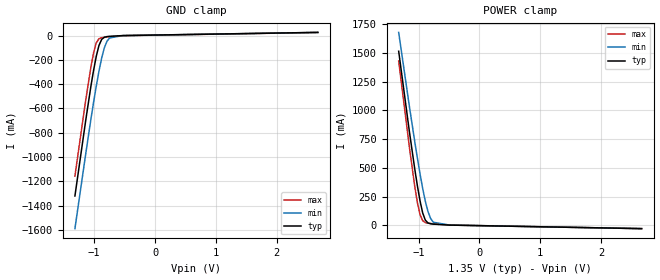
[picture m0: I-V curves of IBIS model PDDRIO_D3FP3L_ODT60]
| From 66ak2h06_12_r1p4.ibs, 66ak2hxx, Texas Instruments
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|   Model PDDRIO_D3FP3L_ODT60
[Model] PDDRIO_D3FP3L_ODT60
Model_type   Input
Polarity   Non-Inverting
Enable   Active-High
C_comp   3.326pF   3.253pF   3.436pF
C_comp_pullup   616.851fF   581.993fF   679.460fF
C_comp_pulldown 2.704pF   2.666pF   2.751pF
Vinh = 810.000mV
Vinl = 540.000mV
[Temperature Range]   25.000   125.000   -40.000
[Voltage Range]   1.350V   1.283V   1.450V
[GND Clamp Reference]   0.00V   0.00V   0.00V
|[C Comp Corner]
| variable   typ   min   max
|C_comp 3.326pF   3.436pF   3.253pF
|C_comp_pullup 616.851fF   679.460fF   581.993fF
|C_comp_pulldown 2.704pF   2.751pF   2.666pF
[POWER Clamp Reference]   1.350V   1.283V   1.450V
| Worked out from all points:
|   GND clamp passes 1 mA (typ) near -0.55 V on its own axis
|   POWER clamp passes 1 mA (typ) near -0.48 V on its own axis
[GND Clamp]
-1.318V   -1.321A    -1.59A     -1.157A
-1.142V   -704.5mA   -980.5mA   -537.9mA
-1.055V   -417.5mA   -689mA     -259.1mA
-1.011V   -286.6mA   -549.7mA   -142.2mA
-966.7mV  -171.3mA   -417.3mA   -60.4mA
-922.7mV  -82.79mA   -295mA     -26.53mA
-878.8mV  -32.67mA   -187.6mA   -18.22mA
-834.9mV  -14.54mA   -102.8mA   -15.06mA
-790.9mV  -9.105mA   -47.54mA   -12.64mA
-747mV    -6.761mA   -19.93mA   -10.37mA
-527.3mV  -543.3uA   -558.5uA   -1.352mA
2.68V     25.6mA     25.48mA    24.97mA
[Power Clamp]
-1.33V    1.516A     1.68A      1.431A
-1.155V   820.9mA    1.04A      685.2mA
-1.067V   496mA      734.4mA    345mA
-1.023V   346.5mA    588.3mA    199.9mA
-978.8mV  213mA      449.2mA    92.62mA
-934.9mV  107.4mA    320.6mA    39.25mA
-890.9mV  43.96mA    207.7mA    22.53mA
-847mV    19.57mA    117.9mA    17.71mA
-803mV    12.4mA     57.72mA    14.99mA
-759.1mV  9.593mA    25.83mA    12.61mA
-495.5mV  1.233mA    1.543mA    1.65mA
2.668V    -29.53mA   -29.66mA   -29.82mA
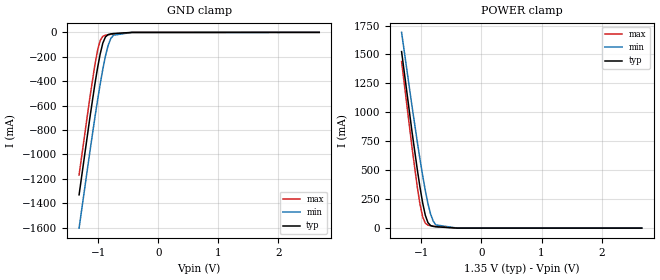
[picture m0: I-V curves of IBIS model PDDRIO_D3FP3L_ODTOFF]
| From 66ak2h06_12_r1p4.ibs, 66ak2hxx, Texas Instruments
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|   Model PDDRIO_D3FP3L_ODTOFF
[Model] PDDRIO_D3FP3L_ODTOFF
Model_type   Input
Polarity   Non-Inverting
Enable   Active-High
C_comp   3.244pF   3.179pF   3.326pF
C_comp_pullup   538.140fF   513.465fF   565.951fF
C_comp_pulldown 2.701pF   2.661pF   2.755pF
Vinh = 810.000mV
Vinl = 540.000mV
[Temperature Range]   25.000   125.000   -40.000
[Voltage Range]   1.350V   1.283V   1.450V
[GND Clamp Reference]   0.00V   0.00V   0.00V
|[C Comp Corner]
| variable   typ   min   max
|C_comp 3.244pF   3.326pF   3.179pF
|C_comp_pullup 538.140fF   565.951fF   513.465fF
|C_comp_pulldown 2.701pF   2.755pF   2.661pF
[POWER Clamp Reference]   1.350V   1.283V   1.450V
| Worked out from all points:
|   GND clamp passes 1 mA (typ) near -0.49 V on its own axis
|   POWER clamp passes 1 mA (typ) near -0.46 V on its own axis
[GND Clamp]
-1.318V   -1.332A    -1.605A    -1.169A
-1.142V   -713.1mA   -991.3mA   -546.4mA
-1.055V   -424.6mA   -698mA     -266.3mA
-1.011V   -292.9mA   -557.9mA   -149mA
-966.7mV  -177mA     -424.6mA   -66.54mA
-922.7mV  -87.81mA   -301.3mA   -32.09mA
-878.8mV  -37.14mA   -193.2mA   -23.25mA
-834.9mV  -18.49mA   -107.6mA   -19.58mA
-790.9mV  -12.57mA   -51.47mA   -16.65mA
-747mV    -9.756mA   -23.13mA   -13.9mA
-439.4mV  -371uA     -394.7uA   -656.8uA
2.68V     4.17nA     252.6nA    716.2pA
[Power Clamp]
-1.33V    1.525A     1.691A     1.439A
-1.155V   827.2mA    1.048A     691.5mA
-1.067V   501.3mA    740.6mA    350.5mA
-1.023V   351.3mA    593.8mA    204.8mA
-978.8mV  217.4mA    454mA      97mA
-934.9mV  111.2mA    324.7mA    43.08mA
-890.9mV  47.28mA    211.3mA    25.9mA
-847mV    22.44mA    121mA      20.68mA
-803mV    14.88mA    60.26mA    17.58mA
-759.1mV  11.71mA    27.92mA    14.82mA
-407.6mV  326.4uA    576uA      395.5uA
2.668V    -7.545nA   -288.5nA   -1.636nA
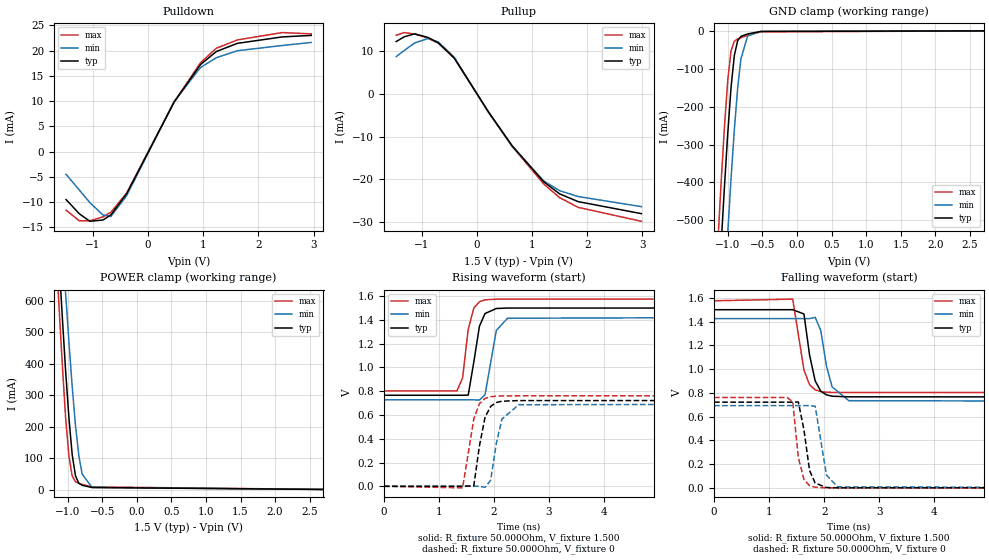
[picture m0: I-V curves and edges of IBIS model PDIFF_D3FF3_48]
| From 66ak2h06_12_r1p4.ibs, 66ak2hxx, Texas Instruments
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|   Model PDIFF_D3FF3_48
[Model] PDIFF_D3FF3_48
Model_type   I/O
Polarity   Non-Inverting
Enable   Active-High
C_comp   3.251pF   3.188pF   3.332pF
C_comp_pullup   516.830fF   493.667fF   544.031fF
C_comp_pulldown 2.728pF   2.688pF   2.782pF
Vinh = 925.000mV
Vinl = 575.000mV
Vmeas = 750.000mV
Vref = 750.000mV
Rref = 50Ohms
Cref = 0pF
[Model Spec]
Vinh   925.000mV   888.000mV   963.000mV
Vinl   575.000mV   538.000mV   613.000mV
Vmeas   750.000mV   713.000mV   788.000mV
Vref   750.000mV   713.000mV   788.000mV
[Temperature Range]   25.000   125.000   -40.000
[Voltage Range]   1.500V   1.425V   1.575V
[GND Clamp Reference]   0.00V   0.00V   0.00V
|[C Comp Corner]
| variable   typ   min   max
|C_comp   3.251pF   3.332pF   3.188pF
|C_comp_pullup   516.830fF   544.031fF   493.667fF
|C_comp_pulldown   2.728pF   2.782pF   2.688pF
[Pulldown Reference]   0.00V   0.00V   0.00V
[POWER Clamp Reference]   1.500V   1.425V   1.575V
[Pullup Reference]   1.500V   1.425V   1.575V
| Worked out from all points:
|   slope of the pulldown table from 0 to 0.225 V, typ, clamps not added: 46.4 ohm
|   slope of the pullup table from 0 to 0.225 V, typ, clamps not added: 50 ohm
|   GND clamp passes 1 mA (typ) near -0.49 V on its own axis
|   POWER clamp passes 1 mA (typ) near -0.46 V on its own axis
|   rising waveform, R_fixture 50.000Ohm, V_fixture 1.500: 20-80 % time 157ps typ, 162ps min, 148ps max; typ from 0.766 V to 1.5 V
|   rising waveform, R_fixture 50.000Ohm, V_fixture 0: 20-80 % time 160ps typ, 170ps min, 172ps max; typ from 0 V to 0.722 V
|   falling waveform, R_fixture 50.000Ohm, V_fixture 1.500: 20-80 % time 165ps typ, 182ps min, 175ps max; typ from 1.5 V to 0.766 V
|   falling waveform, R_fixture 50.000Ohm, V_fixture 0: 20-80 % time 142ps typ, 150ps min, 134ps max; typ from 0.722 V to 0 V
[GND Clamp]
-1.48V    -1.923A    -2.185A    -1.768A
-1.145V   -724.9mA   -1.004A    -557.8mA
-1.098V   -564.4mA   -842.1mA   -400mA
-1.05V    -411.2mA   -684.6mA   -253.6mA
-1.002V   -269.9mA   -533mA     -130.2mA
-954.6mV  -149.3mA   -390.1mA   -52.62mA
-906.8mV  -64.83mA   -260.5mA   -27.54mA
-859.1mV  -26.07mA   -151.7mA   -21.41mA
-811.4mV  -14.62mA   -73.8mA    -17.99mA
-715.9mV  -8.247mA   -13.8mA    -12.04mA
-525mV    -1.646mA   -1.444mA   -2.745mA
2.959V    5.164nA    157.9nA    5.12nA
[Power Clamp]
-1.459V   2.086A     2.205A     2.044A
-1.173V   911.3mA    1.129A     779.1mA
-1.125V   725.7mA    956.4mA    581.8mA
-1.077V   546.8mA    787.6mA    395.5mA
-1.03V    378.5mA    624.4mA    230.1mA
-981.8mV  228.3mA    469.3mA    106.6mA
-934.1mV  110.5mA    326.5mA    43.38mA
-886.4mV  43.33mA    203mA      25.09mA
-838.6mV  20.28mA    108.4mA    20.04mA
-790.9mV  13.81mA    49.59mA    16.81mA
-647.7mV  6.615mA    6.928mA    8.547mA
2.98V     -9.151nA   -320.3nA   -14.09nA
[Pulldown]
-1.48V    -9.5mA     -4.5mA     -11.6mA
-1.241V   -12.3mA    -7.6mA     -13.7mA
-1.05V    -13.8mA    -10.1mA    -13.7mA
-811.4mV  -13.54mA   -12.56mA   -12.92mA
-668.2mV  -12.54mA   -12.85mA   -12.01mA
-381.8mV  -8.308mA   -8.696mA   -8.191mA
477.3mV   9.811mA    9.914mA    9.851mA
954.6mV   17.24mA    16.65mA    17.6mA
1.241V    19.81mA    18.59mA    20.46mA
1.623V    21.43mA    19.97mA    22.1mA
2.434V    22.7mA     21mA       23.56mA
2.959V    23mA       21.6mA     23.3mA
[Pullup]
-1.459V   12.2mA     8.686mA    13.67mA
-1.316V   13.3mA     10.09mA    14.3mA
-1.125V   14mA       11.87mA    13.96mA
-886.4mV  13.17mA    12.9mA     13.01mA
-695.5mV  11.9mA     12.1mA     11.8mA
-409.1mV  8.359mA    8.568mA    8.345mA
211.4mV   -4.231mA   -4.335mA   -4.267mA
640.9mV   -12.14mA   -12.32mA   -12.3mA
1.214V    -20.59mA   -20.38mA   -21.1mA
1.5V      -23.38mA   -22.64mA   -24.26mA
1.834V    -25.19mA   -24mA      -26.53mA
2.98V     -28mA      -26.36mA   -29.79mA
[Ramp]
R_load=50.000Ohm
dV/dt_r   436.650mV/150.000ps  416.999mV/159.500ps  460.020mV/141.000ps
dV/dt_f   436.650mV/142.000ps  416.999mV/153.000ps  460.020mV/136.000ps
[Rising waveform]
R_fixture=50.000Ohm
V_fixture=1.500
V_fixture_min=1.425
V_fixture_max=1.575
0s        766mV      727.3mV    802.9mV
1.327ns   766mV      727.3mV    802.9mV
1.429ns   766.1mV    727.3mV    912.5mV
1.531ns   767.1mV    727.3mV    1.321V
1.633ns   1.046V     727.4mV    1.5V
1.735ns   1.347V     725.6mV    1.553V
1.837ns   1.454V     770.9mV    1.569V
2.042ns   1.496V     1.312V     1.575V
2.246ns   1.5V       1.414V     1.575V
10ns      1.5V       1.425V     1.575V
[Rising waveform]
R_fixture=50.000Ohm
V_fixture=0
0s        0V         2.363uV    0V
1.429ns   32.45uV    -4.13uV    -13.22mV
1.633ns   5.131mV    14.55uV    567.1mV
1.735ns   340.3mV    442.7uV    695.4mV
1.837ns   580.9mV    -9.356mV   739.6mV
1.939ns   672.6mV    51.26mV    753.9mV
2.042ns   704.9mV    361.7mV    758.8mV
2.144ns   715.9mV    566.2mV    760.4mV
2.45ns    721.3mV    686.4mV    761.3mV
10ns      721.5mV    692.3mV    761.3mV
[Falling waveform]
R_fixture=50.000Ohm
V_fixture=1.500
V_fixture_min=1.425
V_fixture_max=1.575
0s        1.5V       1.425V     1.575V
1.429ns   1.5V       1.425V     1.589V
1.633ns   1.464V     1.425V     992.3mV
1.735ns   1.119V     1.425V     868.4mV
1.837ns   900.4mV    1.436V     825.3mV
1.939ns   814.3mV    1.324V     810.5mV
2.042ns   782.8mV    1.026V     805.5mV
2.144ns   771.8mV    850.7mV    803.9mV
2.45ns    766.3mV    733.9mV    803mV
10ns      766mV      727.3mV    802.9mV
[Falling waveform]
R_fixture=50.000Ohm
V_fixture=0
0s        721.5mV    692.3mV    761.3mV
1.327ns   721.5mV    692.3mV    761.3mV
1.429ns   721.6mV    692.3mV    725.1mV
1.531ns   723.1mV    692.3mV    255.6mV
1.633ns   488.5mV    692.3mV    70.38mV
1.735ns   146.2mV    692.3mV    18.6mV
1.837ns   40.42mV    687.8mV    4.983mV
2.042ns   3.03mV     107.6mV    297.5uV
2.246ns   211.2uV    8.423mV    15.22uV
10ns      0V         2.37uV     0V
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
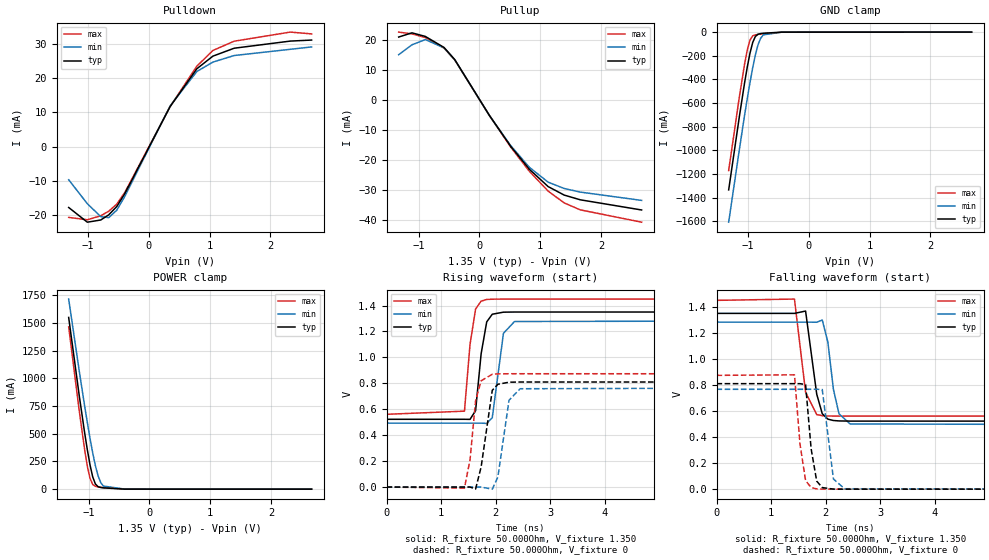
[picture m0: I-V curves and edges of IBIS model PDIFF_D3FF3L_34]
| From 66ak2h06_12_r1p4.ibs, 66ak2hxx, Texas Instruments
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|   Model PDIFF_D3FF3L_34
[Model] PDIFF_D3FF3L_34
Model_type   I/O
Polarity   Non-Inverting
Enable   Active-High
C_comp   3.258pF   3.193pF   3.341pF
C_comp_pullup   525.132fF   499.417fF   553.259fF
C_comp_pulldown 2.727pF   2.688pF   2.781pF
Vinh = 810.000mV
Vinl = 540.000mV
Vmeas = 675.000mV
Vref = 675.000mV
Rref = 50Ohms
Cref = 0pF
[Model Spec]
Vinh   810.000mV   777.000mV   860.000mV
Vinl   540.000mV   507.000mV   590.000mV
Vmeas   675.000mV   642.000mV   725.000mV
Vref   675.000mV   642.000mV   725.000mV
[Temperature Range]   25.000   125.000   -40.000
[Voltage Range]   1.350V   1.283V   1.450V
[GND Clamp Reference]   0.00V   0.00V   0.00V
|[C Comp Corner]
| variable   typ   min   max
|C_comp 3.258pF   3.341pF   3.193pF
|C_comp_pullup 525.132fF   553.259fF   499.417fF
|C_comp_pulldown 2.727pF   2.781pF   2.688pF
[Pulldown Reference]   0.00V   0.00V   0.00V
[POWER Clamp Reference]   1.350V   1.283V   1.450V
[Pullup Reference]   1.350V   1.283V   1.450V
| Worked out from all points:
|   slope of the pulldown table from 0 to 0.203 V, typ, clamps not added: 29.1 ohm
|   slope of the pullup table from 0 to 0.203 V, typ, clamps not added: 31.5 ohm
|   GND clamp passes 1 mA (typ) near -0.49 V on its own axis
|   POWER clamp passes 1 mA (typ) near -0.46 V on its own axis
|   rising waveform, R_fixture 50.000Ohm, V_fixture 1.350: 20-80 % time 144ps typ, 151ps min, 136ps max; typ from 0.523 V to 1.35 V
|   rising waveform, R_fixture 50.000Ohm, V_fixture 0: 20-80 % time 144ps typ, 157ps min, 141ps max; typ from 0 V to 0.81 V
|   falling waveform, R_fixture 50.000Ohm, V_fixture 1.350: 20-80 % time 158ps typ, 164ps min, 143ps max; typ from 1.35 V to 0.523 V
|   falling waveform, R_fixture 50.000Ohm, V_fixture 0: 20-80 % time 131ps typ, 139ps min, 130ps max; typ from 0.81 V to 0 V
[GND Clamp]
-1.318V   -1.335A    -1.608A    -1.171A
-1.142V   -714.5mA   -993.4mA   -547.6mA
-1.055V   -425.4mA   -699.4mA   -266.8mA
-1.011V   -293.4mA   -558.9mA   -149.2mA
-966.7mV  -177.2mA   -425.4mA   -66.61mA
-922.7mV  -87.91mA   -301.8mA   -32.11mA
-878.8mV  -37.17mA   -193.5mA   -23.26mA
-834.9mV  -18.49mA   -107.7mA   -19.59mA
-790.9mV  -12.57mA   -51.5mA    -16.66mA
-747mV    -9.759mA   -23.14mA   -13.91mA
-439.4mV  -371uA     -394.7uA   -656.8uA
2.68V     4.178nA    252.7nA    4.262nA
[Power Clamp]
-1.33V    1.55A      1.716A     1.465A
-1.155V   840mA      1.063A     702.7mA
-1.067V   508.3mA    750.7mA    355.3mA
-1.023V   355.7mA    601.6mA    207mA
-978.8mV  219.6mA    459.6mA    97.64mA
-934.9mV  112mA      328.4mA    43.17mA
-890.9mV  47.41mA    213.3mA    25.91mA
-847mV    22.45mA    121.8mA    20.7mA
-803mV    14.88mA    60.5mA     17.59mA
-759.1mV  11.72mA    27.97mA    14.84mA
-407.6mV  326.5uA    576.1uA    395.6uA
2.668V    -7.545nA   -288.5nA   -10.01nA
[Pulldown]
-1.318V   -17.8mA    -9.7mA     -20.7mA
-1.011V   -22.1mA    -16.7mA    -21.4mA
-790.9mV  -21.46mA   -20.47mA   -20.23mA
-659.1mV  -19.96mA   -20.78mA   -18.9mA
-527.3mV  -17.54mA   -18.61mA   -16.82mA
-395.5mV  -13.8mA    -14.61mA   -13.44mA
351.5mV   11.67mA    11.86mA    11.67mA
790.9mV   22.71mA    21.91mA    23.46mA
1.055V    26.4mA     24.66mA    28.06mA
1.406V    28.72mA    26.59mA    30.77mA
2.329V    30.8mA     28.4mA     33.43mA
2.68V     31.1mA     29.1mA     32.9mA
[Pullup]
-1.33V    20.9mA     15.02mA    22.55mA
-1.111V   22.3mA     18.32mA    21.95mA
-890.9mV  21.1mA     20.05mA    20.73mA
-583.3mV  17.43mA    17.29mA    17.22mA
-407.6mV  13.39mA    13.38mA    13.29mA
163.6mV   -5.23mA    -5.208mA   -5.267mA
515.1mV   -15.54mA   -15.31mA   -15.79mA
822.7mV   -23.18mA   -22.52mA   -23.86mA
1.13V     -28.91mA   -27.44mA   -30.42mA
1.394V    -31.74mA   -29.54mA   -34.35mA
1.658V    -33.31mA   -30.74mA   -36.66mA
2.668V    -36.7mA    -33.51mA   -40.77mA
[Ramp]
R_load=50.000Ohm
dV/dt_r   491.310mV/128.000ps  467.070mV/138.500ps  528.870mV/117.000ps
dV/dt_f   491.310mV/118.500ps  467.070mV/129.000ps  528.870mV/109.500ps
[Rising waveform]
R_fixture=50.000Ohm
V_fixture=1.350
V_fixture_min=1.283
V_fixture_max=1.450
0s        522.6mV    493.1mV    561.2mV
1.429ns   522.7mV    493.1mV    585.4mV
1.531ns   522mV      493.2mV    1.1V
1.633ns   589.1mV    493.2mV    1.373V
1.735ns   1.029V     493.1mV    1.434V
1.837ns   1.274V     490.4mV    1.447V
1.939ns   1.333V     534.8mV    1.449V
2.144ns   1.349V     1.186V     1.45V
2.348ns   1.35V      1.277V     1.45V
10ns      1.35V      1.283V     1.45V
[Rising waveform]
R_fixture=50.000Ohm
V_fixture=0
0s        0V         1.612uV    0V
1.429ns   -3.936uV   -2.453uV   -8.266mV
1.531ns   279.7uV    3.59uV     210.2mV
1.633ns   -15.5mV    -5.992uV   665.4mV
1.735ns   155.6mV    15.34uV    819.6mV
1.939ns   746.2mV    -16.27mV   870mV
2.042ns   792.8mV    76.93mV    873mV
2.246ns   808.6mV    669.6mV    874mV
2.45ns    810.2mV    758.4mV    874.1mV
10ns      810.3mV    767mV      874.1mV
[Falling waveform]
R_fixture=50.000Ohm
V_fixture=1.350
V_fixture_min=1.283
V_fixture_max=1.450
0s        1.35V      1.283V     1.45V
1.429ns   1.35V      1.283V     1.46V
1.633ns   1.368V     1.283V     743.3mV
1.837ns   730.2mV    1.282V     573mV
1.939ns   579.4mV    1.299V     564.4mV
2.042ns   537.8mV    1.128V     562mV
2.144ns   527.2mV    765.1mV    561.4mV
2.246ns   524.1mV    578.8mV    561.2mV
2.45ns    522.7mV    500.8mV    561.2mV
10ns      522.6mV    493.1mV    561.2mV
[Falling waveform]
R_fixture=50.000Ohm
V_fixture=0
0s        810.3mV    767mV      874.1mV
1.429ns   810.3mV    767mV      878.2mV
1.531ns   810.1mV    767mV      344.7mV
1.633ns   803.6mV    767mV      66.17mV
1.735ns   309.2mV    767mV      12.3mV
1.837ns   61.77mV    767.3mV    2.295mV
1.939ns   12.2mV     765.1mV    410.8uV
2.144ns   432.5uV    77.89mV    9.722uV
2.348ns   12.5uV     3.34mV     0V
10ns      0V         1.612uV    0V
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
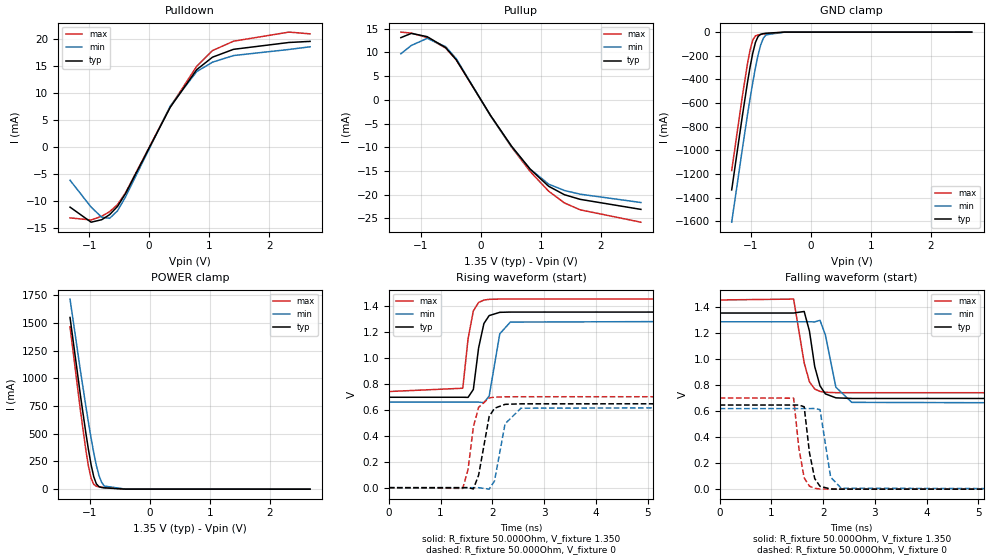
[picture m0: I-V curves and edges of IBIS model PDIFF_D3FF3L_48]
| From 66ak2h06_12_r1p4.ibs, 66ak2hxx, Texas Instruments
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|   Model PDIFF_D3FF3L_48
[Model] PDIFF_D3FF3L_48
Model_type   I/O
Polarity   Non-Inverting
Enable   Active-High
C_comp   3.258pF   3.193pF   3.341pF
C_comp_pullup   525.132fF   499.417fF   553.259fF
C_comp_pulldown 2.727pF   2.688pF   2.781pF
Vinh = 810.000mV
Vinl = 540.000mV
Vmeas = 675.000mV
Vref = 675.000mV
Rref = 50Ohms
Cref = 0pF
[Model Spec]
Vinh   810.000mV   777.000mV   860.000mV
Vinl   540.000mV   507.000mV   590.000mV
Vmeas   675.000mV   642.000mV   725.000mV
Vref   675.000mV   642.000mV   725.000mV
[Temperature Range]   25.000   125.000   -40.000
[Voltage Range]   1.350V   1.283V   1.450V
[GND Clamp Reference]   0.00V   0.00V   0.00V
|[C Comp Corner]
| variable   typ   min   max
|C_comp 3.258pF   3.341pF   3.193pF
|C_comp_pullup 525.132fF   553.259fF   499.417fF
|C_comp_pulldown 2.727pF   2.781pF   2.688pF
[Pulldown Reference]   0.00V   0.00V   0.00V
[POWER Clamp Reference]   1.350V   1.283V   1.450V
[Pullup Reference]   1.350V   1.283V   1.450V
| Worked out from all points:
|   slope of the pulldown table from 0 to 0.203 V, typ, clamps not added: 46.1 ohm
|   slope of the pullup table from 0 to 0.203 V, typ, clamps not added: 49.9 ohm
|   GND clamp passes 1 mA (typ) near -0.49 V on its own axis
|   POWER clamp passes 1 mA (typ) near -0.46 V on its own axis
|   rising waveform, R_fixture 50.000Ohm, V_fixture 1.350: 20-80 % time 158ps typ, 164ps min, 148ps max; typ from 0.695 V to 1.35 V
|   rising waveform, R_fixture 50.000Ohm, V_fixture 0: 20-80 % time 172ps typ, 180ps min, 165ps max; typ from 0 V to 0.645 V
|   falling waveform, R_fixture 50.000Ohm, V_fixture 1.350: 20-80 % time 186ps typ, 193ps min, 182ps max; typ from 1.35 V to 0.695 V
|   falling waveform, R_fixture 50.000Ohm, V_fixture 0: 20-80 % time 146ps typ, 151ps min, 143ps max; typ from 0.645 V to 0 V
[GND Clamp]
-1.318V   -1.335A    -1.608A    -1.171A
-1.142V   -714.5mA   -993.4mA   -547.6mA
-1.055V   -425.4mA   -699.4mA   -266.8mA
-1.011V   -293.4mA   -558.9mA   -149.2mA
-966.7mV  -177.2mA   -425.4mA   -66.61mA
-922.7mV  -87.91mA   -301.8mA   -32.11mA
-878.8mV  -37.17mA   -193.5mA   -23.26mA
-834.9mV  -18.49mA   -107.7mA   -19.59mA
-790.9mV  -12.57mA   -51.5mA    -16.66mA
-747mV    -9.759mA   -23.14mA   -13.91mA
-439.4mV  -371uA     -394.7uA   -656.8uA
2.68V     4.175nA    252.7nA    2.48nA
[Power Clamp]
-1.33V    1.55A      1.716A     1.465A
-1.155V   840mA      1.063A     702.7mA
-1.067V   508.3mA    750.7mA    355.3mA
-1.023V   355.7mA    601.6mA    207mA
-978.8mV  219.6mA    459.6mA    97.64mA
-934.9mV  112mA      328.4mA    43.17mA
-890.9mV  47.41mA    213.3mA    25.91mA
-847mV    22.45mA    121.8mA    20.7mA
-803mV    14.88mA    60.5mA     17.59mA
-759.1mV  11.72mA    27.97mA    14.84mA
-407.6mV  326.5uA    576.1uA    395.6uA
2.668V    -7.545nA   -288.5nA   -6.01nA
[Pulldown]
-1.318V   -11.2mA    -6.2mA     -13.2mA
-966.7mV  -14mA      -11.2mA    -13.59mA
-790.9mV  -13.54mA   -13.07mA   -12.9mA
-659.1mV  -12.6mA    -13.28mA   -12.05mA
-527.3mV  -11.07mA   -11.89mA   -10.73mA
-395.5mV  -8.712mA   -9.343mA   -8.571mA
351.5mV   7.366mA    7.582mA    7.448mA
790.9mV   14.34mA    13.99mA    14.96mA
1.055V    16.67mA    15.74mA    17.9mA
1.406V    18.13mA    16.97mA    19.64mA
2.329V    19.4mA     18.1mA     21.33mA
2.68V     19.6mA     18.6mA     21mA
[Pullup]
-1.33V    13.1mA     9.71mA     14.27mA
-1.155V   14mA       11.46mA    14.05mA
-890.9mV  13.3mA     12.95mA    13.12mA
-583.3mV  10.99mA    11.19mA    10.89mA
-407.6mV  8.447mA    8.666mA    8.41mA
163.6mV   -3.298mA   -3.373mA   -3.333mA
515.1mV   -9.801mA   -9.917mA   -9.993mA
822.7mV   -14.62mA   -14.58mA   -15.1mA
1.13V     -18.22mA   -17.77mA   -19.25mA
1.394V    -20.01mA   -19.12mA   -21.74mA
1.658V    -20.99mA   -19.9mA    -23.2mA
2.668V    -23.1mA    -21.65mA   -25.8mA
[Ramp]
R_load=50.000Ohm
dV/dt_r   389.940mV/155.500ps  372.929mV/165.500ps  422.970mV/143.000ps
dV/dt_f   389.940mV/150.000ps  372.929mV/161.500ps  422.970mV/139.000ps
[Rising waveform]
R_fixture=50.000Ohm
V_fixture=1.350
V_fixture_min=1.283
V_fixture_max=1.450
0s        695mV      657.5mV    739.1mV
1.429ns   695.1mV    657.5mV    764.4mV
1.531ns   694.2mV    657.5mV    1.145V
1.633ns   755mV      657.6mV    1.359V
1.735ns   1.075V     657.5mV    1.424V
1.837ns   1.262V     653.8mV    1.442V
1.939ns   1.323V     704.3mV    1.448V
2.144ns   1.348V     1.183V     1.45V
2.348ns   1.35V      1.273V     1.45V
10ns      1.35V      1.283V     1.45V
[Rising waveform]
R_fixture=50.000Ohm
V_fixture=0
0s        0V         2.106uV    0V
1.429ns   0V         -1.991uV   -5.874mV
1.531ns   202.2uV    3.777uV    141.3mV
1.633ns   -10.16mV   -1.078uV   467mV
1.735ns   96.03mV    10.94uV    617.8mV
1.939ns   547.2mV    -11.58mV   689.7mV
2.042ns   610.6mV    51.66mV    695.8mV
2.246ns   640.5mV    490.3mV    698.6mV
2.552ns   644.5mV    611mV      699mV
10ns      644.8mV    617.6mV    699mV
[Falling waveform]
R_fixture=50.000Ohm
V_fixture=1.350
V_fixture_min=1.283
V_fixture_max=1.450
0s        1.35V      1.283V     1.45V
1.429ns   1.35V      1.283V     1.457V
1.633ns   1.362V     1.283V     967.5mV
1.735ns   1.211V     1.283V     822.5mV
1.837ns   939.3mV    1.282V     767.7mV
1.939ns   791.9mV    1.294V     749.3mV
2.042ns   730.5mV    1.183V     742.6mV
2.246ns   699.9mV    781.4mV    739.6mV
2.552ns   695.3mV    665.3mV    739.2mV
10ns      695mV      657.5mV    739.1mV
[Falling waveform]
R_fixture=50.000Ohm
V_fixture=0
0s        644.8mV    617.6mV    699mV
1.429ns   644.8mV    617.6mV    697.7mV
1.531ns   644.7mV    617.6mV    312.1mV
1.633ns   631.6mV    617.6mV    86.25mV
1.735ns   280.3mV    617.5mV    23.11mV
1.837ns   80.79mV    618.2mV    6.082mV
1.939ns   21.91mV    609.3mV    1.603mV
2.144ns   1.598mV    92.25mV    102.1uV
2.348ns   109.6uV    7.162mV    3.083uV
10ns      0V         2.099uV    0V
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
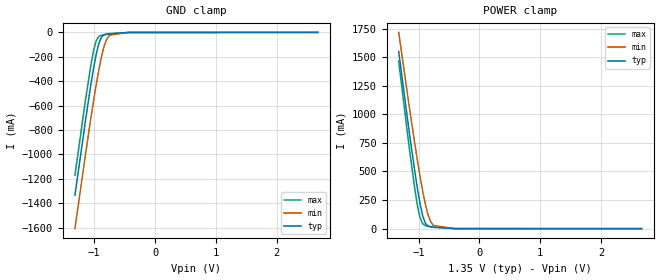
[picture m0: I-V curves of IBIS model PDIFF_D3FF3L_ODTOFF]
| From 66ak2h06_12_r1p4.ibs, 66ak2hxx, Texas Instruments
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|   Model PDIFF_D3FF3L_ODTOFF
[Model] PDIFF_D3FF3L_ODTOFF
Model_type   Input
Polarity   Non-Inverting
Enable   Active-High
C_comp   3.258pF   3.193pF   3.341pF
C_comp_pullup   538.338fF   513.686fF   566.201fF
C_comp_pulldown 2.714pF   2.674pF   2.769pF
Vinh = 810.000mV
Vinl = 540.000mV
[Temperature Range]   25.000   125.000   -40.000
[Voltage Range]   1.350V   1.283V   1.450V
[GND Clamp Reference]   0.00V   0.00V   0.00V
|[C Comp Corner]
| variable   typ   min   max
|C_comp 3.258pF   3.341pF   3.193pF
|C_comp_pullup 538.338fF   566.201fF   513.686fF
|C_comp_pulldown 2.714pF   2.769pF   2.674pF
[POWER Clamp Reference]   1.350V   1.283V   1.450V
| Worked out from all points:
|   GND clamp passes 1 mA (typ) near -0.49 V on its own axis
|   POWER clamp passes 1 mA (typ) near -0.46 V on its own axis
[GND Clamp]
-1.318V   -1.335A    -1.608A    -1.171A
-1.142V   -714.5mA   -993.4mA   -547.6mA
-1.055V   -425.4mA   -699.4mA   -266.8mA
-1.011V   -293.4mA   -558.9mA   -149.2mA
-966.7mV  -177.2mA   -425.4mA   -66.61mA
-922.7mV  -87.91mA   -301.8mA   -32.11mA
-878.8mV  -37.17mA   -193.5mA   -23.26mA
-834.9mV  -18.49mA   -107.7mA   -19.59mA
-790.9mV  -12.57mA   -51.5mA    -16.66mA
-747mV    -9.759mA   -23.14mA   -13.91mA
-439.4mV  -371uA     -394.7uA   -656.8uA
2.68V     4.175nA    252.7nA    695pA
[Power Clamp]
-1.33V    1.55A      1.716A     1.465A
-1.155V   840mA      1.063A     702.7mA
-1.067V   508.3mA    750.7mA    355.3mA
-1.023V   355.7mA    601.6mA    207mA
-978.8mV  219.6mA    459.6mA    97.64mA
-934.9mV  112mA      328.4mA    43.17mA
-890.9mV  47.41mA    213.3mA    25.91mA
-847mV    22.45mA    121.8mA    20.7mA
-803mV    14.88mA    60.5mA     17.59mA
-759.1mV  11.72mA    27.97mA    14.84mA
-407.6mV  326.5uA    576.1uA    395.6uA
2.668V    -7.545nA   -288.5nA   -1.638nA
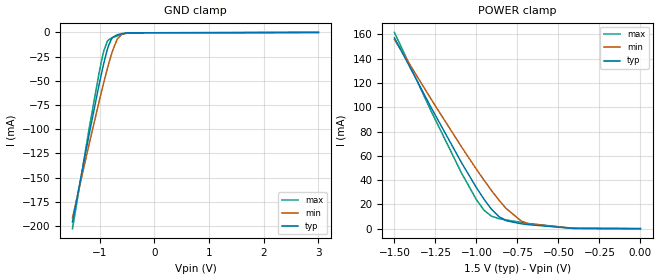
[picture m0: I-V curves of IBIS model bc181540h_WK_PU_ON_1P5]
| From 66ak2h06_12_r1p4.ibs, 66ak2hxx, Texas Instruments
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|   Model Cell bc181540h_WK_PU_ON_1P5
|bc181540h_WK_PU_ON_1P5
[Model]   bc181540h_WK_PU_ON_1P5
Model_type   Input
Polarity   Non-Inverting
Vinl =  0.525
Vinh =  0.975
C_comp   1.17072p   0.570099p   1.17447p
[Model Spec]
Vinl   0.525   0.4725   0.5775
Vinh   0.975   0.8775   1.0725
[Temperature Range]   25   125   -40
[Voltage Range]   1.5   1.35   1.65
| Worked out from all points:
|   GND clamp passes 1 mA (typ) near -0.57 V on its own axis
|   POWER clamp passes 1 mA (typ) near -0.52 V on its own axis
[POWER_clamp]
|   voltage   I(typ)   I(min)   I(max)
-1.5V     157.3mA    155.9mA    161.7mA
-1.273V   98.99mA    106mA      95.93mA
-1.091V   54.41mA    67.42mA    45.88mA
-1V       33.77mA    48.97mA    23.85mA
-954.5mV  24.39mA    40.12mA    15.35mA
-909.1mV  16.17mA    31.63mA    10.33mA
-863.6mV  10.01mA    23.7mA     8.31mA
-818.2mV  6.543mA    16.55mA    7.143mA
-727.3mV  4.034mA    6.373mA    5.146mA
-681.8mV  3.265mA    3.899mA    4.212mA
-409.1mV  202.5uA    273.6uA    263.9uA
0V        673.5pA    15.91nA    183.3pA
[GND_clamp]
|   voltage   I(typ)   I(min)   I(max)
-1.5V     -195.7mA   -191.7mA   -202.7mA
-1.197V   -105.9mA   -115.9mA   -100.2mA
-1.015V   -54.7mA    -72.08mA   -42.56mA
-954.5mV  -38.76mA   -58.03mA   -25.64mA
-924.2mV  -31.37mA   -51.22mA   -18.82mA
-863.6mV  -17.82mA   -37.96mA   -9.172mA
-833.3mV  -12.67mA   -31.74mA   -7.525mA
-772.7mV  -5.481mA   -20.06mA   -5.488mA
-681.8mV  -2.457mA   -6.993mA   -3.582mA
-590.9mV  -1.213mA   -1.644mA   -1.959mA
-500mV    -440.4uA   -422.4uA   -777.6uA
3V        0A         0A         0A
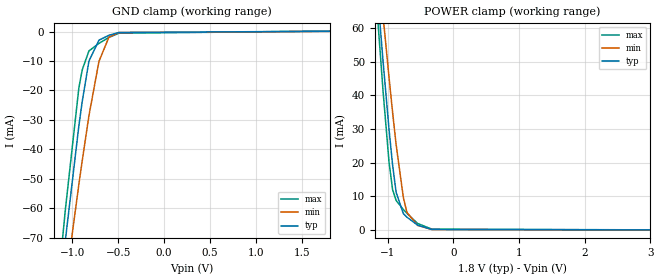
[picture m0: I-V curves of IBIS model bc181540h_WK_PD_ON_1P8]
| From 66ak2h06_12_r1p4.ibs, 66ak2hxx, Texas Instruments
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|   Model Cell bc181540h_WK_PD_ON_1P8
|bc181540h_WK_PD_ON_1P8
[Model]   bc181540h_WK_PD_ON_1P8
Model_type   Input
Polarity   Non-Inverting
Vinl =  0.63
Vinh =  1.17
C_comp   1.16613p   0.553312p   1.16742p
[Model Spec]
Vinl   0.63   0.567   0.693
Vinh   1.17   1.053   1.287
[Temperature Range]   25   125   -40
[Voltage Range]   1.8   1.62   1.98
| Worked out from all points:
|   GND clamp passes 1 mA (typ) near -0.58 V on its own axis
|   POWER clamp passes 1 mA (typ) near -0.51 V on its own axis
[POWER_clamp]
|   voltage   I(typ)   I(min)   I(max)
-1.8V     236mA      223mA      250.9mA
-1.164V   71.99mA    82.72mA    65.55mA
-1.127V   63.19mA    75.06mA    55.7mA
-1.073V   50.29mA    63.74mA    41.44mA
-981.8mV  30mA       45.44mA    20.27mA
-927.3mV  19.35mA    35.01mA    12.01mA
-872.7mV  11.13mA    25.28mA    8.756mA
-763.6mV  4.856mA    9.681mA    6.09mA
-709.1mV  3.816mA    5.243mA    4.935mA
-545.5mV  1.43mA     1.352mA    1.926mA
-327.3mV  148.6uA    124.5uA    233.2uA
3.6V      0A         0A         0A
[GND_clamp]
|   voltage   I(typ)   I(min)   I(max)
-1.8V     -286.5mA   -268.3mA   -306.4mA
-1.182V   -101.5mA   -112.2mA   -95.14mA
-1.145V   -91.01mA   -103.3mA   -83.2mA
-1.109V   -80.69mA   -94.46mA   -71.53mA
-1.073V   -70.48mA   -85.72mA   -60.04mA
-927.3mV  -31.94mA   -51.84mA   -19.05mA
-890.9mV  -23.71mA   -43.86mA   -12.98mA
-818.2mV  -10.04mA   -28.6mA    -6.585mA
-709.1mV  -2.912mA   -10.13mA   -4.001mA
-600mV    -1.238mA   -1.858mA   -1.976mA
-490.9mV  -310.9uA   -325.7uA   -560.5uA
1.8V      109.9uA    66.18uA    174.2uA
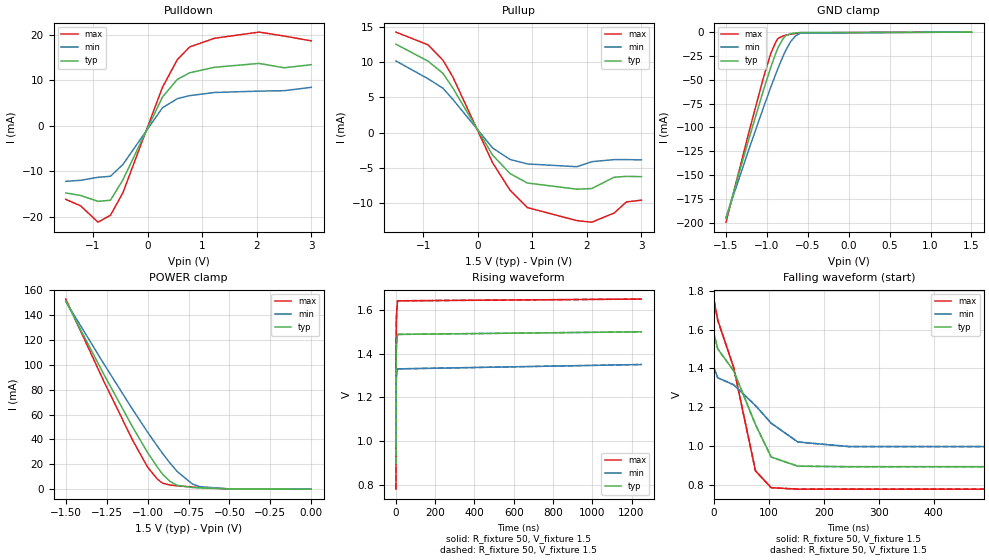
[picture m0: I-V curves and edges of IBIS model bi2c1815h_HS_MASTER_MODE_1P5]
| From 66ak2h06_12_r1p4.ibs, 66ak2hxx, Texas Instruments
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|   Model Cell bi2c1815h_HS_MASTER_MODE_1P5
|bi2c1815h_HS_MASTER_MODE_1P5
[Model]   bi2c1815h_HS_MASTER_MODE_1P5
Model_type   I/O
Polarity   Non-Inverting
Enable   Active-Low
Vinl =  0.45
Vinh =  1.05
Cref =  15.0000pF
Rref =  100.0000M
Vref =  0V
Vmeas =  0.75
C_comp   7.63862p   2.44169p   8.22121p
[Model Spec]
Vinl   0.45   0.405   0.495
Vinh   1.05   0.945   1.155
[Temperature Range]   25   125   -40
[Voltage Range]   1.5   1.35   1.65
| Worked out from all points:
|   slope of the pulldown table from 0 to 0.225 V, typ, clamps not added: 41.5 ohm
|   slope of the pullup table from 0 to 0.225 V, typ, clamps not added: 84.4 ohm
|   GND clamp passes 1 mA (typ) near -0.66 V on its own axis
|   POWER clamp passes 1 mA (typ) near -0.68 V on its own axis
|   rising waveform, R_fixture 50, V_fixture 1.5: 20-80 % time 659ps typ, 898ps min, 679ps max; typ from 0.894 V to 1.5 V
|   rising waveform, R_fixture 50, V_fixture 1.5: 20-80 % time 659ps typ, 898ps min, 679ps max; typ from 0.894 V to 1.5 V
|   falling waveform, R_fixture 50, V_fixture 1.5: 20-80 % time 50.7ns typ, 71.7ns min, 39ns max; typ from 1.5 V to 0.894 V
|   falling waveform, R_fixture 50, V_fixture 1.5: 20-80 % time 50.7ns typ, 71.7ns min, 39ns max; typ from 1.5 V to 0.894 V
[POWER_clamp]
|   voltage   I(typ)   I(min)   I(max)
-1.5V     151mA      150.9mA    152.8mA
-1.273V   93.69mA    101.9mA    88.24mA
-1.091V   49.77mA    63.93mA    39.17mA
-1V       29.43mA    45.82mA    17.67mA
-939.4mV  17.53mA    34.37mA    7.927mA
-909.1mV  12.18mA    28.82mA    4.843mA
-863.6mV  6.238mA    21.05mA    3.309mA
-818.2mV  3.071mA    14.07mA    2.668mA
-727.3mV  1.364mA    4.256mA    1.737mA
-681.8mV  1.02mA     2.019mA    1.336mA
-500mV    171uA      194.3uA    230.4uA
0V        214.9pA    5.588nA    92.88pA
[Pulldown]
|   voltage   I(typ)   I(min)   I(max)
-1.5V     -14.74mA   -12.19mA   -16.16mA
-1.227V   -15.31mA   -11.97mA   -17.6mA
-909.1mV  -16.6mA    -11.3mA    -21.18mA
-681.8mV  -16.35mA   -11.08mA   -19.67mA
-454.5mV  -11.91mA   -8.507mA   -14.74mA
272.7mV   6.362mA    3.997mA    8.501mA
545.5mV   10.24mA    5.996mA    14.59mA
772.7mV   11.69mA    6.665mA    17.39mA
1.227V    12.9mA     7.352mA    19.28mA
2.045V    13.75mA    7.657mA    20.64mA
2.5V      12.79mA    7.745mA    19.78mA
3V        13.46mA    8.49mA     18.71mA
[Pullup]
|   voltage   I(typ)   I(min)   I(max)
-1.5V     12.51mA    10.14mA    14.22mA
-909.1mV  10.1mA     7.613mA    12.41mA
-636.4mV  8.377mA    6.274mA    10.23mA
-454.5mV  6.288mA    4.687mA    7.842mA
272.7mV   -3.163mA   -2.172mA   -4.258mA
590.9mV   -5.779mA   -3.783mA   -8.124mA
909.1mV   -7.123mA   -4.423mA   -10.59mA
1.818V    -7.993mA   -4.815mA   -12.44mA
2.091V    -7.905mA   -4.106mA   -12.66mA
2.5V      -6.299mA   -3.81mA    -11.37mA
2.727V    -6.18mA    -3.81mA    -9.787mA
3V        -6.22mA    -3.85mA    -9.55mA
[GND_clamp]
|   voltage   I(typ)   I(min)   I(max)
-1.5V     -195.5mA   -194.1mA   -199.3mA
-1.227V   -113.8mA   -124.5mA   -107mA
-1.045V   -61.55mA   -79.59mA   -48.43mA
-954.5mV  -37.21mA   -58.07mA   -22.7mA
-893.9mV  -22.74mA   -44.36mA   -10.65mA
-863.6mV  -16.14mA   -37.7mA    -6.624mA
-803mV    -6.914mA   -25.34mA   -4.002mA
-772.7mV  -3.892mA   -19.56mA   -3.316mA
-712.1mV  -1.754mA   -10.17mA   -2.298mA
-651.5mV  -919.5uA   -3.984mA   -1.444mA
-590.9mV  -443.7uA   -1.105mA   -766.2uA
1.5V      214.9pA    164.2nA    51.74pA
[Ramp]
| variable   typ   min   max
dV/dt_f   0.407994/59.490494n   0.239838/83.236524n   0.588018/46.436378n
dV/dt_r  0.2817132/49.951926n  0.1724844/80.348704n   0.419322/30.862359n
R_load = 50
[Rising Waveform]
R_fixture = 50
V_fixture = 1.5
V_fixture_min = 1.35
V_fixture_max = 1.65
|   time   V(typ)   V(min)   V(max)
0s        893.7mV    997mV      778.7mV
379ps     915mV      999.8mV    816.5mV
566.7ps   959.2mV    1.007V     1.131V
708.6ps   1.099V     1.017V     1.369V
936.8ps   1.321V     1.056V     1.465V
1.571ns   1.385V     1.273V     1.483V
2.522ns   1.432V     1.291V     1.557V
4.121ns   1.45V      1.317V     1.596V
8.324ns   1.488V     1.33V      1.642V
1.25us    1.5V       1.35V      1.65V
[Rising Waveform]
R_fixture = 50
V_fixture = 1.5
V_fixture_min = 1.35
V_fixture_max = 1.65
|   time   V(typ)   V(min)   V(max)
0s        893.7mV    997mV      778.7mV
379ps     915mV      999.8mV    816.5mV
566.7ps   959.2mV    1.007V     1.131V
708.6ps   1.099V     1.017V     1.369V
936.8ps   1.321V     1.056V     1.465V
1.571ns   1.385V     1.273V     1.483V
2.522ns   1.432V     1.291V     1.557V
4.121ns   1.45V      1.317V     1.596V
8.324ns   1.488V     1.33V      1.642V
1.25us    1.5V       1.35V      1.65V
[Falling Waveform]
R_fixture = 50
V_fixture = 1.5
V_fixture_min = 1.35
V_fixture_max = 1.65
|   time   V(typ)   V(min)   V(max)
0s        1.5V       1.35V      1.65V
437ps     1.565V     1.355V     1.758V
1.099ns   1.57V      1.397V     1.742V
7.259ns   1.501V     1.352V     1.649V
36.17ns   1.388V     1.316V     1.405V
75.86ns   1.111V     1.209V     872.4mV
104.4ns   943.5mV    1.118V     785.4mV
153ns     896.2mV    1.021V     777.9mV
245.6ns   893.7mV    997.5mV    777.8mV
1.25us    893.7mV    997mV      777.8mV
[Falling Waveform]
R_fixture = 50
V_fixture = 1.5
V_fixture_min = 1.35
V_fixture_max = 1.65
|   time   V(typ)   V(min)   V(max)
0s        1.5V       1.35V      1.65V
437ps     1.565V     1.355V     1.758V
1.099ns   1.57V      1.397V     1.742V
7.259ns   1.501V     1.352V     1.649V
36.17ns   1.388V     1.316V     1.405V
75.86ns   1.111V     1.209V     872.4mV
104.4ns   943.5mV    1.118V     785.4mV
153ns     896.2mV    1.021V     777.9mV
245.6ns   893.7mV    997.5mV    777.8mV
1.25us    893.7mV    997mV      777.8mV
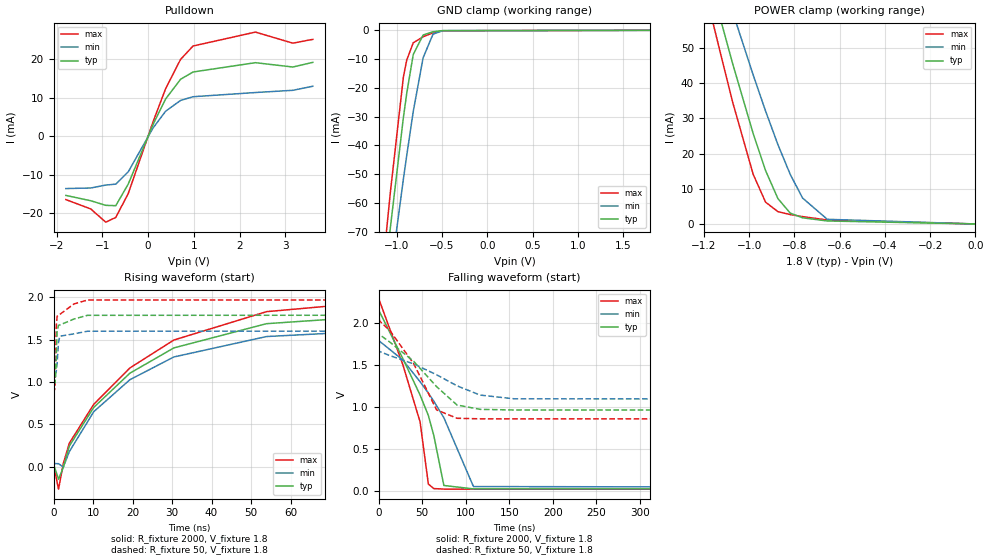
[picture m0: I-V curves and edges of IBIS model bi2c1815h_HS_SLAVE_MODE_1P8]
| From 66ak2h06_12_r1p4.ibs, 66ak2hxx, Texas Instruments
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|   Model Cell bi2c1815h_HS_SLAVE_MODE_1P8
|bi2c1815h_HS_SLAVE_MODE_1P8
[Model]   bi2c1815h_HS_SLAVE_MODE_1P8
Model_type   I/O_open_drain
Polarity   Non-Inverting
Enable   Active-Low
Vinl =  0.54
Vinh =  1.26
Cref =  15.0000pF
Rref =  100.0000M
Vref =  1.8
Vmeas =  0.9
C_comp   7.82904p   2.84791p   8.43627p
[Model Spec]
Vinl   0.54   0.486   0.594
Vinh   1.26   1.134   1.386
[Temperature Range]   25   125   -40
[Voltage Range]   1.8   1.62   1.98
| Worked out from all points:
|   slope of the pulldown table from 0 to 0.27 V, typ, clamps not added: 37.1 ohm
|   GND clamp passes 1 mA (typ) near -0.66 V on its own axis
|   POWER clamp passes 1 mA (typ) near -0.68 V on its own axis
|   rising waveform, R_fixture 2000, V_fixture 1.8: 20-80 % time 27.3ns typ, 25.2ns min, 29.6ns max; typ from 0.029 V to 1.8 V
|   rising waveform, R_fixture 50, V_fixture 1.8: 20-80 % time 381ps typ, 489ps min, 355ps max; typ from 0.966 V to 1.8 V
|   falling waveform, R_fixture 2000, V_fixture 1.8: 20-80 % time 34.1ns typ, 45.6ns min, 28.1ns max; typ from 1.8 V to 0.029 V
|   falling waveform, R_fixture 50, V_fixture 1.8: 20-80 % time 44.8ns typ, 61ns min, 35.5ns max; typ from 1.8 V to 0.966 V
[POWER_clamp]
|   voltage   I(typ)   I(min)   I(max)
-1.8V     228.3mA    217.1mA    239.9mA
-1.182V   71.41mA    82.7mA     63.22mA
-1.164V   67.02mA    78.9mA     58.31mA
-1.127V   58.34mA    71.38mA    48.65mA
-1.073V   45.63mA    60.27mA    34.69mA
-981.8mV  25.64mA    42.31mA    14.07mA
-927.3mV  15.19mA    32.09mA    6.201mA
-872.7mV  7.212mA    22.55mA    3.494mA
-818.2mV  3.071mA    14.07mA    2.668mA
-763.6mV  1.749mA    7.355mA    2.087mA
-654.5mV  846uA      1.319mA    1.117mA
0V        320.1pA    6.203nA    1.2nA
[Pulldown]
|   voltage   I(typ)   I(min)   I(max)
-1.8V     -15.34mA   -13.56mA   -16.43mA
-1.255V   -16.73mA   -13.41mA   -18.86mA
-927.3mV  -17.92mA   -12.65mA   -22.3mA
-709.1mV  -18.01mA   -12.41mA   -21.06mA
-436.4mV  -12.4mA    -9.209mA   -14.87mA
109.1mV   3.162mA    2.233mA    3.875mA
381.8mV   9.743mA    6.546mA    12.41mA
709.1mV   14.85mA    9.354mA    20.03mA
981.8mV   16.74mA    10.31mA    23.49mA
2.345V    19.16mA    11.4mA     27.11mA
3.164V    18.03mA    11.98mA    24.23mA
3.6V      19.24mA    13.03mA    25.22mA
[GND_clamp]
|   voltage   I(typ)   I(min)   I(max)
-1.8V     -287mA     -272.2mA   -302.8mA
-1.182V   -100.5mA   -113.1mA   -91.98mA
-1.145V   -89.92mA   -104mA     -80.05mA
-1.109V   -79.52mA   -95.11mA   -68.4mA
-1.073V   -69.22mA   -86.23mA   -56.94mA
-927.3mV  -30.39mA   -51.8mA    -16.31mA
-890.9mV  -22.12mA   -43.71mA   -10.41mA
-818.2mV  -8.424mA   -28.23mA   -4.346mA
-709.1mV  -1.635mA   -9.541mA   -2.241mA
-600mV    -499.1uA   -1.337mA   -852.9uA
-490.9mV  -80.16uA   -133.6uA   -148.6uA
1.8V      320.1pA    340nA      252.2pA
[Ramp]
| variable   typ   min   max
dV/dt_f   0.536928/49.188593n   0.34098/66.438503n   0.721968/39.462855n
dV/dt_r 44.521095m/0.13594334n 28.120458m/0.15816159n 61.281425m/0.14135556n
R_load = 50
[Rising Waveform]
R_fixture = 2000
V_fixture = 1.8
V_fixture_min = 1.62
V_fixture_max = 1.98
|   time   V(typ)   V(min)   V(max)
0s        29.49mV    37.05mV    26.77mV
1.267ns   -148.7mV   34.3mV     -266.4mV
2.473ns   -10.92mV   -4.471mV   35.86mV
4.001ns   243.4mV    177.6mV    277.1mV
10.18ns   699.6mV    649mV      736.1mV
19.33ns   1.104V     1.027V     1.166V
30.47ns   1.403V     1.296V     1.496V
53.9ns    1.689V     1.537V     1.831V
82.54ns   1.78V      1.606V     1.95V
1.25us    1.8V       1.62V      1.98V
[Rising Waveform]
R_fixture = 50
V_fixture = 1.8
V_fixture_min = 1.62
V_fixture_max = 1.98
|   time   V(typ)   V(min)   V(max)
0s        966.2mV    1.092V     862.3mV
373.8ps   993.7mV    1.097V     935.2mV
513.2ps   1.053V     1.105V     1.214V
685.9ps   1.306V     1.126V     1.651V
908.6ps   1.607V     1.216V     1.777V
1.253ns   1.669V     1.471V     1.791V
1.599ns   1.674V     1.541V     1.799V
5.162ns   1.744V     1.569V     1.922V
8.595ns   1.788V     1.6V       1.969V
1.25us    1.8V       1.62V      1.98V
[Falling Waveform]
R_fixture = 2000
V_fixture = 1.8
V_fixture_min = 1.62
V_fixture_max = 1.98
|   time   V(typ)   V(min)   V(max)
0s        1.8V       1.62V      1.98V
416.5ps   1.961V     1.621V     2.283V
838.5ps   2.135V     1.784V     2.266V
27.7ns    1.578V     1.56V      1.506V
47.54ns   1.144V     1.302V     824.7mV
57.03ns   901.1mV    1.167V     87.64mV
63.28ns   664mV      1.071V     33.85mV
74.85ns   70.54mV    874.3mV    27.73mV
108.8ns   29.73mV    57.88mV    26.78mV
1.25us    29.49mV    37.05mV    26.74mV
[Falling Waveform]
R_fixture = 50
V_fixture = 1.8
V_fixture_min = 1.62
V_fixture_max = 1.98
|   time   V(typ)   V(min)   V(max)
0s        1.8V       1.62V      1.98V
485.3ps   1.859V     1.633V     2.065V
1.168ns   1.86V      1.66V      2.022V
12.81ns   1.772V     1.612V     1.909V
40.2ns    1.544V     1.513V     1.516V
66.57ns   1.243V     1.384V     967.5mV
90ns      1.025V     1.253V     868mV
116.6ns   974mV      1.143V     861.6mV
155.9ns   966.5mV    1.099V     861.3mV
1.25us    966.2mV    1.092V     861.3mV
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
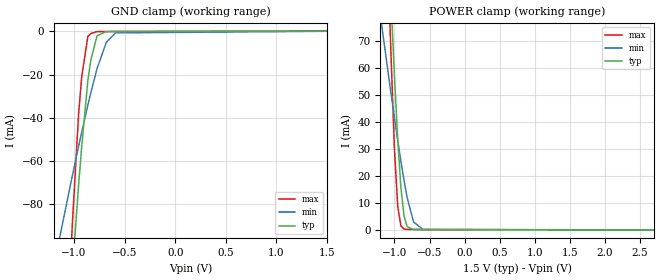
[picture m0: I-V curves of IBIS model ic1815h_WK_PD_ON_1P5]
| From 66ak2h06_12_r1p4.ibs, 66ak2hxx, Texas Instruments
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|   Model Cell ic1815h_WK_PD_ON_1P5
|ic1815ghypbfbh.ibs   [27Dec11 revision 1.0]
|ic1815ghypbfbh
|WK_PD_ON_1P5
[Model]   ic1815h_WK_PD_ON_1P5
Model_type   Input
Polarity   Non-Inverting
Vinl =  0.525
Vinh =  0.975
C_comp   0.756654p   0.691399p   0.775102p
[Model Spec]
Vinl   0.525   0.4725   0.5775
Vinh   0.975   0.8775   1.0725
[Temperature Range]   25   125   -40
[Voltage Range]   1.5   1.35   1.65
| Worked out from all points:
|   GND clamp passes 1 mA (typ) near -0.74 V on its own axis
|   POWER clamp passes 1 mA (typ) near -0.81 V on its own axis
[POWER_clamp]
|   voltage   I(typ)   I(min)   I(max)
-1.5V     376.7mA    139.2mA    483.4mA
-1.182V   165.8mA    75.71mA    178.2mA
-1.061V   90.99mA    52.54mA    73.17mA
-1.03V    73.52mA    46.91mA    50.51mA
-1V       56.61mA    41.36mA    29.65mA
-954.5mV  33.91mA    33.28mA    8.892mA
-909.1mV  15.84mA    25.53mA    1.556mA
-863.6mV  5.096mA    18.31mA    353.7uA
-818.2mV  1.208mA    11.85mA    209.4uA
-727.3mV  148.9uA    2.951mA    190uA
-590.9mV  109.6uA    142.8uA    186.2uA
3V        0A         0A         0A
[GND_clamp]
|   voltage   I(typ)   I(min)   I(max)
-1.5V     -462.9mA   -179.8mA   -593.8mA
-1.227V   -259.3mA   -114.9mA   -299.5mA
-1.045V   -129.9mA   -73.09mA   -115mA
-1.015V   -109.6mA   -66.33mA   -87.48mA
-954.5mV  -70.66mA   -53.01mA   -37.76mA
-924.2mV  -53.15mA   -46.56mA   -20.87mA
-863.6mV  -22.58mA   -34.02mA   -2.252mA
-833.3mV  -12.95mA   -28.15mA   -988.6uA
-772.7mV  -2.026mA   -17.17mA   -111.2uA
-681.8mV  -118uA     -5.11mA    -71.37uA
-590.9mV  -40.49uA   -686.6uA   -61.71uA
1.5V      87.58uA    48.5uA     143.3uA
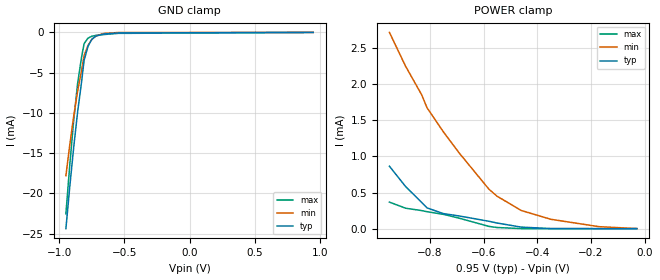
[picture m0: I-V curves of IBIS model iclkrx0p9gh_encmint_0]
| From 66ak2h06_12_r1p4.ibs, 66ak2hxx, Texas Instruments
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|   Model Cell iclkrx0p9gh_encmint_0
|iclkrx0p9gh_encmint_0.ibs   [10Feb12 revision 1.0]
|iclkrx0p9gh_encmint_0
[Model]   iclkrx0p9gh_encmint_0
Model_type   Input
Polarity   Non-Inverting
Vinl =  1.15
Vinh =  1.25
C_comp   1p   1p   1p
[Model Spec]
Vinl   1.15   1.15   1.15
Vinh   1.25   1.25   1.25
[Temperature Range]   25   125   -40
[Voltage Range]   0.95   0.81   0.998
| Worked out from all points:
|   GND clamp passes 1 mA (typ) near -0.76 V on its own axis
[GND_clamp]
|   voltage   I(typ)   I(min)   I(max)
-950mV    -24.37mA   -17.8mA    -22.52mA
-920mV    -19.13mA   -13.94mA   -16.43mA
-890mV    -14.26mA   -10.41mA   -10.93mA
-860mV    -9.89mA    -7.313mA   -6.346mA
-830mV    -6.209mA   -4.769mA   -3.109mA
-810mV    -3.448mA   -2.865mA   -1.386mA
-780mV    -1.721mA   -1.599mA   -707.3uA
-750mV    -842uA     -854.1uA   -468.7uA
-720mV    -452.4uA   -451.9uA   -371.1uA
-660mV    -201uA     -135.3uA   -268.2uA
-550mV    -69.96uA   -16.21uA   -120.7uA
950mV     5.853nA    774.1nA    8.111nA
[POWER_clamp]
|   voltage   I(typ)   I(min)   I(max)
-950mV    863.9uA    2.715mA    367.2uA
-890mV    583.2uA    2.248mA    283.1uA
-830mV    362.2uA    1.852mA    249.9uA
-810mV    287.3uA    1.672mA    234.8uA
-750mV    209uA      1.343mA    198.8uA
-690mV    175.3uA    1.045mA    144.4uA
-580mV    102.2uA    546.6uA    31.4uA
-550mV    78.15uA    450.1uA    16.02uA
-460mV    21.58uA    251.9uA    846.4nA
-350mV    966.4nA    129.8uA    20.52nA
-170mV    10.26nA    27.33uA    10.66nA
-30mV     6.168nA    1.548uA    8.455nA
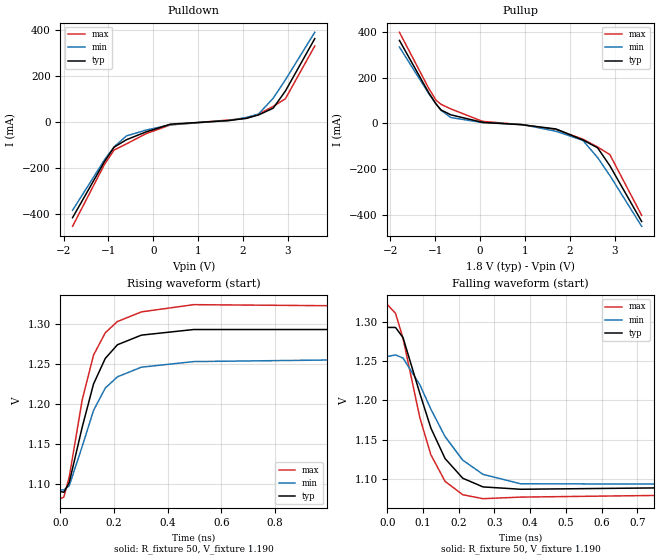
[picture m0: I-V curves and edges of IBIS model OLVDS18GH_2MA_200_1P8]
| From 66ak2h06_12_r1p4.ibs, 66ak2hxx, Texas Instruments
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|   Model Cell OLVDS18GH_2MA_200_1P8
|olvds18gh.ibs [30Dec11 revision 1.0]
|OLVDS18GH_2MA_200_1P8
[Model]   OLVDS18GH_2MA_200_1P8
Model_type   Output
Polarity   Non-Inverting
Cref =  15.0001pF
Rref =  101.0000M
Vref =  0V
Vmeas =  1.08V
C_comp   1p   1p   1p
[Temperature Range]   25   125   -40
[Voltage Range]   1.8   1.62   1.98
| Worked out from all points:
|   slope of the pulldown table from 0 to 0.27 V, typ, clamps not added: 14.9 ohm
|   slope of the pullup table from 0 to 0.27 V, typ, clamps not added: 46.8 ohm
|   rising waveform, R_fixture 50, V_fixture 1.190: 20-80 % time 105ps typ, 113ps min, 95.1ps max; typ from 1.09 V to 1.29 V
|   falling waveform, R_fixture 50, V_fixture 1.190: 20-80 % time 90.9ps typ, 120ps min, 76.7ps max; typ from 1.29 V to 1.09 V
| Nom Voltages:
[Pulldown]
|   voltage   I(typ)   I(min)   I(max)
-1.8V     -415mA     -382.9mA   -452.6mA
-1.091V   -172.1mA   -164.4mA   -184.3mA
-872.7mV  -108.2mA   -106.7mA   -120.7mA
-600mV    -76.16mA   -59.51mA   -94.21mA
-163.6mV  -42.2mA    -34.29mA   -49.86mA
381.8mV   -8.301mA   -10.95mA   -11.63mA
1.691V    7.477mA    7.657mA    10.05mA
2.073V    17.1mA     20.87mA    16.88mA
2.345V    31.61mA    35.59mA    34.95mA
2.673V    61.22mA    104.4mA    68.98mA
2.945V    135.8mA    184.4mA    102.1mA
3.6V      363.5mA    391.3mA    331.6mA
[Pullup]
|   voltage   I(typ)   I(min)   I(max)
-1.8V     363.2mA    334.2mA    398.8mA
-1.145V   133.3mA    129.7mA    152.6mA
-981.8mV  84.39mA    83.71mA    101mA
-872.7mV  58.76mA    56.69mA    83.17mA
-654.5mV  37.37mA    25.53mA    63.21mA
54.55mV   4.241mA    3.155mA    8.601mA
927.3mV   -6.031mA   -4.663mA   -5.838mA
1.691V    -24.68mA   -34.83mA   -26.72mA
2.291V    -73.1mA    -74.74mA   -69.33mA
2.618V    -107mA     -150mA     -103.4mA
2.891V    -185.5mA   -228.2mA   -136.9mA
3.6V      -429.9mA   -450.9mA   -402.9mA
[Ramp]
| variable   typ   min   max
dV/dt_f   7.464m/1.6812067n   2.586m/0.26678006n   4.35m/0.95694846n
dV/dt_r   4.164m/2.0412997n   1.464m/2.0787797n   3.9m/0.98319863n
R_load = 50
[Rising Waveform]
R_fixture = 50
V_fixture = 1.190
V_fixture_min = 1.1743
V_fixture_max = 1.20176
|   time   V(typ)   V(min)   V(max)
0s        1.091V     1.093V     1.082V
12.7ps    1.09V      1.093V     1.084V
32.7ps    1.102V     1.098V     1.109V
80.9ps    1.171V     1.147V     1.205V
123.2ps   1.225V     1.192V     1.261V
167.1ps   1.257V     1.22V      1.289V
212.4ps   1.274V     1.234V     1.303V
301.6ps   1.286V     1.246V     1.315V
496.4ps   1.293V     1.253V     1.324V
1.262ns   1.293V     1.256V     1.322V
[Falling Waveform]
R_fixture = 50
V_fixture = 1.190
V_fixture_min = 1.1743
V_fixture_max = 1.20176
|   time   V(typ)   V(min)   V(max)
0s        1.293V     1.256V     1.322V
23ps      1.293V     1.258V     1.311V
44ps      1.28V      1.254V     1.279V
91.1ps    1.209V     1.22V      1.178V
121.9ps   1.165V     1.189V     1.131V
161.8ps   1.126V     1.154V     1.097V
211.4ps   1.101V     1.124V     1.08V
267.9ps   1.09V      1.106V     1.075V
373.1ps   1.087V     1.094V     1.077V
1.262ns   1.091V     1.093V     1.082V
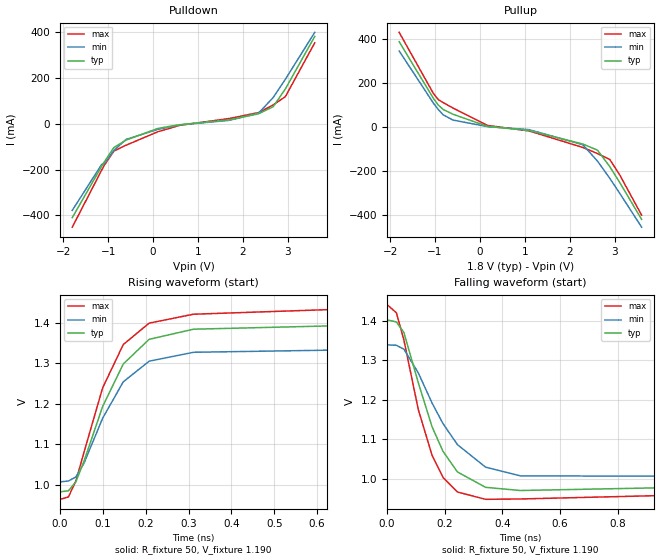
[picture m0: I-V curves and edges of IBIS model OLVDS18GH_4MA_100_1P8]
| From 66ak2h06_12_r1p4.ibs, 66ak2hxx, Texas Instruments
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|   Model Cell OLVDS18GH_4MA_100_1P8
|olvds18gh.ibs [30Dec11 revision 1.0]
|OLVDS18GH_4MA_100_1P8
[Model]   OLVDS18GH_4MA_100_1P8
Model_type   Output
Polarity   Non-Inverting
Cref =  15.0001pF
Rref =  101.0000M
Vref =  0V
Vmeas =  1.08V
C_comp   1p   1p   1p
[Temperature Range]   25   125   -40
[Voltage Range]   1.8   1.62   1.98
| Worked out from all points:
|   slope of the pulldown table from 0 to 0.27 V, typ, clamps not added: 18.9 ohm
|   slope of the pullup table from 0 to 0.27 V, typ, clamps not added: 22.8 ohm
|   rising waveform, R_fixture 50, V_fixture 1.190: 20-80 % time 103ps typ, 98.7ps min, 97.3ps max; typ from 0.982 V to 1.4 V
|   falling waveform, R_fixture 50, V_fixture 1.190: 20-80 % time 115ps typ, 155ps min, 96.3ps max; typ from 1.4 V to 0.982 V
| Nom Voltages:
[Pulldown]
|   voltage   I(typ)   I(min)   I(max)
-1.8V     -409.8mA   -377.9mA   -451.3mA
-1.145V   -185.6mA   -177.5mA   -202.3mA
-1.091V   -168mA     -174.4mA   -182.4mA
-872.7mV  -103.7mA   -116.5mA   -119.1mA
-600mV    -71.26mA   -68.18mA   -93.5mA
109.1mV   -20.25mA   -24.41mA   -34.69mA
600mV     -3.939mA   -4.871mA   -6.762mA
1.691V    16.85mA    14.75mA    22.78mA
2.345V    43.23mA    45.65mA    48.45mA
2.673V    74.26mA    114.1mA    82.01mA
2.945V    151.7mA    193.9mA    118.2mA
3.6V      381.1mA    399mA      353.2mA
[Pullup]
|   voltage   I(typ)   I(min)   I(max)
-1.8V     385.6mA    343.6mA    428mA
-1.036V   128.3mA    106.6mA    150.2mA
-927.3mV  98.02mA    77.92mA    122.8mA
-818.2mV  78.04mA    53.67mA    109.3mA
-600mV    56.54mA    30.16mA    84.75mA
163.6mV   1.812mA    554.8uA    6.034mA
1.091V    -17.12mA   -13.07mA   -18.85mA
2.291V    -78.47mA   -81.49mA   -94.03mA
2.618V    -106.4mA   -156.2mA   -121.6mA
2.891V    -180.9mA   -233.9mA   -148.6mA
3.109V    -251.7mA   -300.8mA   -217.4mA
3.6V      -420.1mA   -455.3mA   -401mA
[Ramp]
| variable   typ   min   max
dV/dt_f   11.946m/0.55026518n   6.834m/0.85554012n   5.538m/0.55872905n
dV/dt_r   5.97m/0.73436703n   7.068m/3.1776707n   5.088m/0.51543102n
R_load = 50
[Rising Waveform]
R_fixture = 50
V_fixture = 1.190
V_fixture_min = 1.1743
V_fixture_max = 1.20176
|   time   V(typ)   V(min)   V(max)
0s        982.4mV    1.007V     963.8mV
19.3ps    984.8mV    1.009V     969.7mV
36.7ps    1.007V     1.019V     1.009V
55.7ps    1.058V     1.053V     1.08V
99.2ps    1.193V     1.164V     1.239V
147.4ps   1.298V     1.254V     1.346V
207.8ps   1.359V     1.305V     1.399V
311.5ps   1.384V     1.327V     1.421V
977ps     1.401V     1.338V     1.445V
4.929ns   1.401V     1.339V     1.442V
[Falling Waveform]
R_fixture = 50
V_fixture = 1.190
V_fixture_min = 1.1743
V_fixture_max = 1.20176
|   time   V(typ)   V(min)   V(max)
0s        1.402V     1.339V     1.441V
32.4ps    1.397V     1.338V     1.42V
58.6ps    1.37V      1.328V     1.351V
108.6ps   1.243V     1.268V     1.175V
156.2ps   1.132V     1.192V     1.06V
194.1ps   1.07V      1.14V      1.004V
244.1ps   1.018V     1.087V     967.3mV
341.9ps   979.1mV    1.03V      948.8mV
462.4ps   971.1mV    1.008V     949.7mV
1.262ns   982.4mV    1.007V     963.9mV
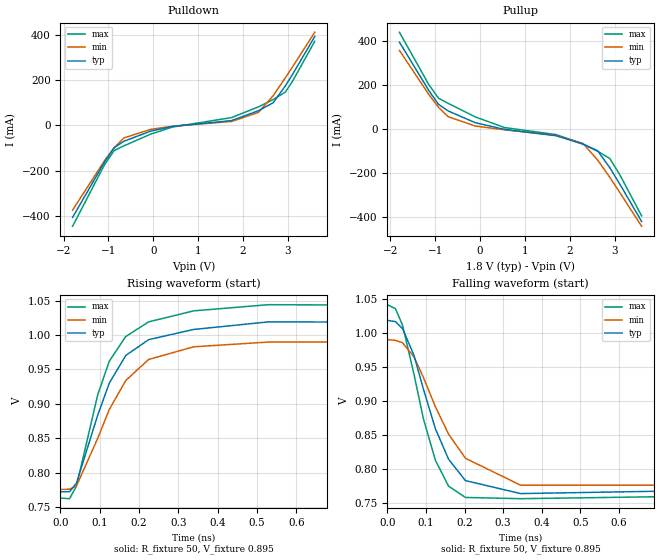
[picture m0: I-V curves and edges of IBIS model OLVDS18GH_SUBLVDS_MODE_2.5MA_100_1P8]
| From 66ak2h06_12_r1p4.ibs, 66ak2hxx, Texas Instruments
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|   Model Cell OLVDS18GH_SUBLVDS_MODE_2.5MA_100_1P8
|olvds18gh.ibs [30Dec11 revision 1.0]
|OLVDS18GH_SUBLVDS_MODE_2.5MA_100_1P8
[Model]   OLVDS18GH_SUBLVDS_MODE_2.5MA_100_1P8
Model_type   Output
Polarity   Non-Inverting
Cref =  15.0001pF
Rref =  101.0000M
Vref =  0V
Vmeas =  1.08V
C_comp   1p   1p   1p
[Temperature Range]   25   125   -40
[Voltage Range]   1.8   1.62   1.98
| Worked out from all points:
|   slope of the pulldown table from 0 to 0.27 V, typ, clamps not added: 20.9 ohm
|   slope of the pullup table from 0 to 0.27 V, typ, clamps not added: 16.7 ohm
|   rising waveform, R_fixture 50, V_fixture 0.895: 20-80 % time 101ps typ, 111ps min, 91.2ps max; typ from 0.772 V to 1.02 V
|   falling waveform, R_fixture 50, V_fixture 0.895: 20-80 % time 84.2ps typ, 114ps min, 69ps max; typ from 1.02 V to 0.772 V
| Nom Voltages:
[Pulldown]
|   voltage   I(typ)   I(min)   I(max)
-1.8V     -408mA     -375.7mA   -447.4mA
-1.091V   -163.7mA   -157.6mA   -175.5mA
-872.7mV  -98.86mA   -98.82mA   -111.5mA
-654.5mV  -70.19mA   -55.41mA   -90.55mA
-54.55mV  -25.04mA   -17.33mA   -38.38mA
436.4mV   -4.276mA   -3.277mA   -6.856mA
1.745V    21.41mA    17.59mA    34.62mA
2.345V    65.31mA    57.83mA    82.34mA
2.673V    100.5mA    131.8mA    114.8mA
2.945V    175.6mA    211.3mA    147.9mA
3.109V    227.7mA    260.9mA    197.5mA
3.6V      394.2mA    413mA      373.2mA
[Pullup]
|   voltage   I(typ)   I(min)   I(max)
-1.8V     396.5mA    358.5mA    441.2mA
-1.145V   176.6mA    158.8mA    203.5mA
-927.3mV  113.5mA    99.75mA    141.5mA
-709.1mV  83.44mA    57.22mA    117.9mA
-109.1mV  30.54mA    15.57mA    56.84mA
545.5mV   42.53uA    -1.837mA   8.36mA
1.691V    -28.5mA    -26.6mA    -23.39mA
2.291V    -66.42mA   -63.46mA   -66.41mA
2.618V    -96.88mA   -138.7mA   -98.96mA
2.891V    -174mA     -217.9mA   -132.2mA
3.109V    -246.8mA   -285.2mA   -204.3mA
3.6V      -418.4mA   -440mA     -392.8mA
[Ramp]
| variable   typ   min   max
dV/dt_f   9.222m/1.1789009n   3.84m/0.91531628n   9.27m/3.0011244n
dV/dt_r   4.59m/1.1610834n   3.828m/3.478069n   11.736m/4.192265n
R_load = 50
[Rising Waveform]
R_fixture = 50
V_fixture = 0.895
V_fixture_min = 0.8825
V_fixture_max = 0.90115
|   time   V(typ)   V(min)   V(max)
0s        772.2mV    775.7mV    763.1mV
23.1ps    772.4mV    775.9mV    762.2mV
40.7ps    784.7mV    780.7mV    780.4mV
94.5ps    883.1mV    849.5mV    912.4mV
124.1ps   929.9mV    891.6mV    961.8mV
166ps     970.2mV    933.8mV    997.7mV
224.4ps   993.2mV    964.4mV    1.019V
338.8ps   1.008V     982.8mV    1.035V
529.1ps   1.019V     989.7mV    1.044V
1.262ns   1.018V     989.8mV    1.042V
[Falling Waveform]
R_fixture = 50
V_fixture = 0.895
V_fixture_min = 0.8825
V_fixture_max = 0.90115
|   time   V(typ)   V(min)   V(max)
0s        1.018V     989.7mV    1.041V
21.1ps    1.016V     988.5mV    1.035V
39.3ps    1.006V     985.1mV    1.011V
68.9ps    966.6mV    964.5mV    939.1mV
93.3ps    917.2mV    934.2mV    873.6mV
124.5ps   858.6mV    891mV      812.2mV
158.5ps   813.9mV    850.9mV    774.3mV
202.3ps   782.4mV    815.2mV    757.6mV
345ps     763.3mV    775.7mV    755.8mV
1.262ns   772.2mV    775.6mV    763.2mV
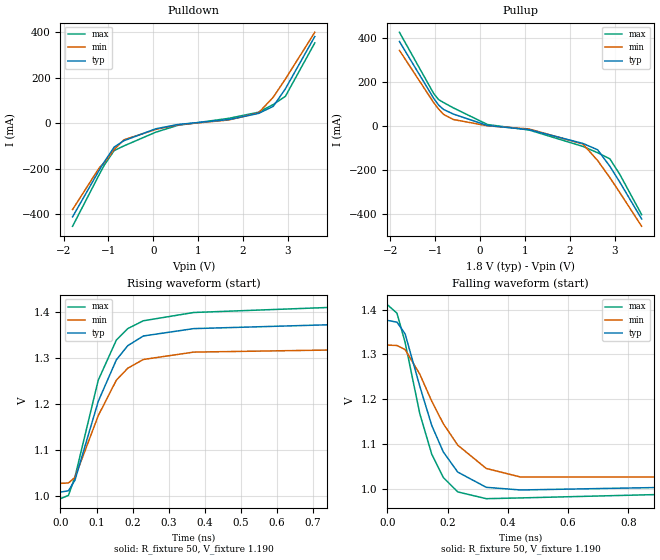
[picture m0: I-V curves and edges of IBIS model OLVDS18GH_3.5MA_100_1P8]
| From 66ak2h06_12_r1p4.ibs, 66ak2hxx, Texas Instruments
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|   Model Cell OLVDS18GH_3.5MA_100_1P8
|olvds18gh.ibs [30Dec11 revision 1.0]
|OLVDS18GH_3.5MA_100_1P8
[Model]   OLVDS18GH_3.5MA_100_1P8
Model_type   Output
Polarity   Non-Inverting
Cref =  15.0001pF
Rref =  101.0000M
Vref =  0V
Vmeas =  1.08V
C_comp   1p   1p   1p
[Temperature Range]   25   125   -40
[Voltage Range]   1.8   1.62   1.98
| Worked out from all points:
|   slope of the pulldown table from 0 to 0.27 V, typ, clamps not added: 18.8 ohm
|   slope of the pullup table from 0 to 0.27 V, typ, clamps not added: 24.4 ohm
|   rising waveform, R_fixture 50, V_fixture 1.190: 20-80 % time 101ps typ, 99.2ps min, 95.5ps max; typ from 1.01 V to 1.38 V
|   falling waveform, R_fixture 50, V_fixture 1.190: 20-80 % time 107ps typ, 146ps min, 89.2ps max; typ from 1.38 V to 1.01 V
| Nom Voltages:
[Pulldown]
|   voltage   I(typ)   I(min)   I(max)
-1.8V     -411.2mA   -379.2mA   -452.8mA
-1.2V     -204.5mA   -194.5mA   -223.7mA
-1.091V   -169.2mA   -173.6mA   -183.7mA
-872.7mV  -105mA     -115.8mA   -120.5mA
-654.5mV  -77mA      -72.96mA   -99.82mA
54.55mV   -24.8mA    -27.72mA   -39.78mA
545.5mV   -6.1mA     -7.395mA   -9.723mA
1.691V    15.84mA    14.05mA    21.4mA
2.345V    42.56mA    44.99mA    47.93mA
2.673V    73.53mA    113.5mA    81.64mA
2.945V    150.7mA    193.4mA    117.7mA
3.6V      380mA      398.8mA    351.9mA
[Pullup]
|   voltage   I(typ)   I(min)   I(max)
-1.8V     384.5mA    344.2mA    426.4mA
-1.036V   126.1mA    106.4mA    147.9mA
-927.3mV  95.85mA    77.68mA    120.6mA
-818.2mV  75.91mA    53.38mA    107.2mA
-600mV    54.73mA    29.94mA    83.02mA
163.6mV   2.553mA    1.215mA    7.023mA
1.091V    -16.12mA   -13.15mA   -17.84mA
2.291V    -78.88mA   -81.68mA   -92.55mA
2.618V    -107.6mA   -156.4mA   -121mA
2.891V    -182.5mA   -234.2mA   -148.8mA
3.109V    -253.6mA   -301mA     -218.1mA
3.6V      -422.3mA   -455.6mA   -402.6mA
[Ramp]
| variable   typ   min   max
dV/dt_f   11.73m/0.86548866n   5.964m/0.86713043n   5.424m/0.5804869n
dV/dt_r   5.814m/0.78003283n   6.348m/3.3037271n   4.992m/0.53974944n
R_load = 50
[Rising Waveform]
R_fixture = 50
V_fixture = 1.190
V_fixture_min = 1.1743
V_fixture_max = 1.20176
|   time   V(typ)   V(min)   V(max)
0s        1.008V     1.027V     993.8mV
22.2ps    1.011V     1.028V     1.001V
40.2ps    1.034V     1.04V      1.041V
104.7ps   1.205V     1.174V     1.251V
154.8ps   1.295V     1.251V     1.338V
186.5ps   1.326V     1.277V     1.363V
229.7ps   1.347V     1.296V     1.38V
369.1ps   1.363V     1.312V     1.398V
950.8ps   1.376V     1.319V     1.415V
4.929ns   1.375V     1.32V      1.411V
[Falling Waveform]
R_fixture = 50
V_fixture = 1.190
V_fixture_min = 1.1743
V_fixture_max = 1.20176
|   time   V(typ)   V(min)   V(max)
0s        1.376V     1.321V     1.411V
32ps      1.372V     1.32V      1.392V
59ps      1.346V     1.311V     1.327V
107.8ps   1.229V     1.256V     1.168V
147.3ps   1.142V     1.196V     1.078V
185.6ps   1.083V     1.146V     1.026V
233.6ps   1.038V     1.098V     993.8mV
328.3ps   1.004V     1.046V     978.7mV
442ps     998.1mV    1.027V     980.4mV
1.262ns   1.008V     1.027V     994mV
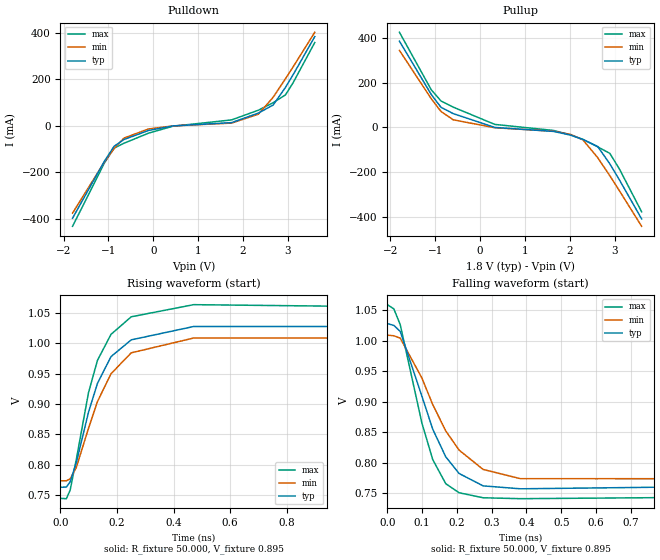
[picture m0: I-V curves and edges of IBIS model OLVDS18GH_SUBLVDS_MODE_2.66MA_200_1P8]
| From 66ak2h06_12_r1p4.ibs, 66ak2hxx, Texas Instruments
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|   Model Cell OLVDS18GH_SUBLVDS_MODE_2.66MA_200_1P8
|olvds18gh.ibs [30Dec11 revision 1.0]
|OLVDS18GH_SUBLVDS_MODE_2.66MA_200_1P8
[Model]   OLVDS18GH_SUBLVDS_MODE_2.66MA_200_1P8
Model_type   Output
Polarity   Non-Inverting
Cref =  15.0001pF
Rref =  101.0000M
Vref =  0V
Vmeas =  1.08V
C_comp   1p   1p   1p
[Temperature Range]   25   125   -40
[Voltage Range]   1.8   1.62   1.98
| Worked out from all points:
|   slope of the pulldown table from 0 to 0.27 V, typ, clamps not added: 25.4 ohm
|   slope of the pullup table from 0 to 0.27 V, typ, clamps not added: 20 ohm
|   rising waveform, R_fixture 50.000, V_fixture 0.895: 20-80 % time 112ps typ, 123ps min, 98.2ps max; typ from 0.763 V to 1.03 V
|   falling waveform, R_fixture 50.000, V_fixture 0.895: 20-80 % time 95.5ps typ, 123ps min, 78.9ps max; typ from 1.03 V to 0.763 V
| Nom Voltages:
[Pulldown]
|   voltage   I(typ)   I(min)   I(max)
-1.8V     -398.4mA   -376.6mA   -433.5mA
-1.091V   -153.3mA   -156.7mA   -160.9mA
-872.7mV  -88.32mA   -97.77mA   -96.35mA
-654.5mV  -59.41mA   -53.44mA   -75.51mA
-109.1mV  -20.55mA   -13.99mA   -32.31mA
436.4mV   -828.7uA   -762.9uA   -2.148mA
1.745V    13.37mA    11.41mA    25.09mA
2.345V    54.7mA     50.09mA    67.09mA
2.673V    89.43mA    122.9mA    99.4mA
2.945V    164.7mA    202mA      132.7mA
3.109V    217mA      251.3mA    182.6mA
3.6V      384.1mA    402.8mA    358.5mA
[Pullup]
|   voltage   I(typ)   I(min)   I(max)
-1.8V     385.3mA    344.3mA    425.3mA
-1.091V   147.4mA    128.2mA    168.5mA
-872.7mV  89.6mA     71.08mA    117.9mA
-600mV    61.52mA    33.82mA    90.48mA
327.3mV   -285.6uA   -1.617mA   13.27mA
1.636V    -17.97mA   -17.21mA   -13.71mA
2.018V    -34.74mA   -31.78mA   -33.41mA
2.291V    -54.23mA   -55.94mA   -53.57mA
2.618V    -85.02mA   -134.8mA   -86.87mA
2.891V    -163.1mA   -216.2mA   -116.2mA
3.109V    -236.5mA   -285mA     -187.9mA
3.6V      -409.4mA   -442.4mA   -377.7mA
[Ramp]
| variable   typ   min   max
dV/dt_f   9.306m/1.4276872n   2.508m/0.21759885n   6.912m/2.9390605n
dV/dt_r   5.028m/1.7149148n   1.902m/0.9012988n   10.452m/4.1949022n
R_load = 50
[Rising Waveform]
R_fixture = 50.000
V_fixture = 0.895
V_fixture_min = 0.882
V_fixture_max = 0.901
|  time   V(typ)   V(min)   V(max)
0s        763mV      773.6mV    744.7mV
20.9ps    763.3mV    773.7mV    744.2mV
34.3ps    772mV      776.9mV    758.2mV
56.1ps    803.6mV    795.6mV    809.2mV
99.3ps    887mV      860.5mV    919.2mV
130.8ps   934.2mV    904.2mV    972.2mV
178.6ps   978.3mV    950.1mV    1.015V
250.2ps   1.006V     984.6mV    1.044V
470.9ps   1.028V     1.009V     1.064V
1.262ns   1.028V     1.009V     1.06V
[Falling Waveform]
R_fixture = 50.000
V_fixture = 0.895
V_fixture_min = 0.882
V_fixture_max = 0.901
|  time   V(typ)   V(min)   V(max)
0s        1.028V     1.009V     1.059V
18.8ps    1.025V     1.008V     1.052V
37.2ps    1.015V     1.004V     1.026V
99.4ps    908.9mV    938.7mV    864.9mV
130.6ps   854.8mV    895.1mV    805mV
168.1ps   809.4mV    851.9mV    765.4mV
206.4ps   782.2mV    820.5mV    750.6mV
275.5ps   761.9mV    788.8mV    742.4mV
383ps     757.1mV    773.7mV    740.9mV
1.262ns   762.9mV    773.6mV    744.7mV
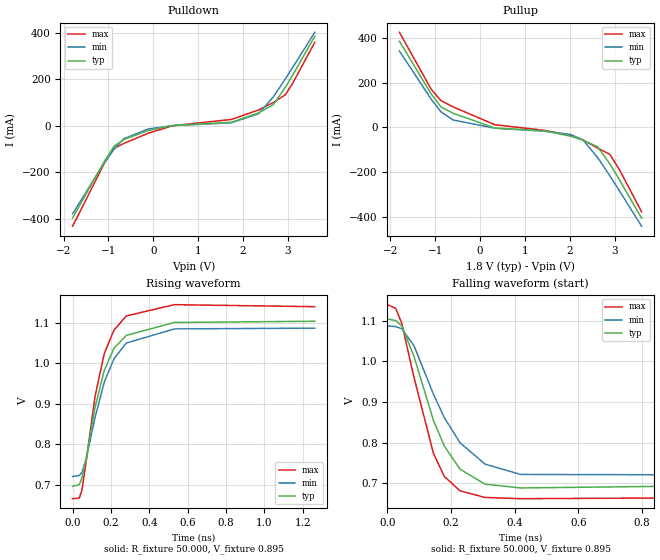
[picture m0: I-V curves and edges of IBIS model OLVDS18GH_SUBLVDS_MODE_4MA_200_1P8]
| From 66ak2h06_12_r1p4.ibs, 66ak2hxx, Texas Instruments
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|   Model Cell OLVDS18GH_SUBLVDS_MODE_4MA_200_1P8
|olvds18gh.ibs [30Dec11 revision 1.0]
|OLVDS18GH_SUBLVDS_MODE_4MA_200_1P8
[Model]   OLVDS18GH_SUBLVDS_MODE_4MA_200_1P8
Model_type   Output
Polarity   Non-Inverting
Cref =  15.0001pF
Rref =  101.0000M
Vref =  0V
Vmeas =  1.08V
C_comp   1p   1p   1p
[Temperature Range]   25   125   -40
[Voltage Range]   1.8   1.62   1.98
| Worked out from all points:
|   slope of the pulldown table from 0 to 0.27 V, typ, clamps not added: 23.1 ohm
|   slope of the pullup table from 0 to 0.27 V, typ, clamps not added: 17.6 ohm
|   rising waveform, R_fixture 50.000, V_fixture 0.895: 20-80 % time 124ps typ, 133ps min, 109ps max; typ from 0.696 V to 1.1 V
|   falling waveform, R_fixture 50.000, V_fixture 0.895: 20-80 % time 109ps typ, 138ps min, 91ps max; typ from 1.1 V to 0.696 V
[Pulldown]
|   voltage   I(typ)   I(min)   I(max)
-1.8V     -396.3mA   -378.4mA   -431.8mA
-1.091V   -152.7mA   -159mA     -161mA
-872.7mV  -87.84mA   -99.94mA   -96.56mA
-654.5mV  -59.11mA   -55.19mA   -75.78mA
-109.1mV  -20.4mA    -13.59mA   -31.85mA
436.4mV   1.074mA    425.8uA    19.8uA
1.745V    14.98mA    12.55mA    27.1mA
2.345V    55.06mA    50.93mA    67.52mA
2.673V    90.01mA    123mA      99.44mA
2.945V    165.2mA    201.5mA    133mA
3.109V    217.4mA    250.5mA    182.8mA
3.6V      384mA      401.2mA    358.1mA
[Pullup]
|   voltage   I(typ)   I(min)   I(max)
-1.8V     386mA      341.7mA    426.1mA
-1.091V   149.4mA    126.3mA    170.5mA
-872.7mV  91.64mA    69.5mA     119.7mA
-600mV    63.18mA    32.99mA    91.68mA
327.3mV   -2.74mA    -3.534mA   11.89mA
1.418V    -14.81mA   -16.83mA   -12.58mA
2.018V    -39.14mA   -31.74mA   -35.35mA
2.291V    -57.5mA    -55.81mA   -55.38mA
2.618V    -86.61mA   -135mA     -92.52mA
2.891V    -163.3mA   -216.5mA   -120.5mA
3.109V    -235.7mA   -285.4mA   -191mA
3.6V      -406.9mA   -442.9mA   -378.3mA
[Ramp]
| variable   typ   min   max
dV/dt_f   9.318m/0.81923825n   5.412m/0.88400714n   11.49m/2.8805185n
dV/dt_r   4.482m/0.89427959n   5.808m/3.3948042n   12.156m/4.1892203n
R_load = 50
[Rising Waveform]
R_fixture = 50.000
V_fixture = 0.895
V_fixture_min = 0.882
V_fixture_max = 0.901
|  time   V(typ)   V(min)   V(max)
0s        696mV      720.2mV    665.3mV
34.6ps    699.7mV    722.4mV    666.6mV
48.7ps    716.2mV    730.6mV    686.2mV
70.7ps    765.2mV    762.8mV    756.5mV
117ps     890.5mV    865.6mV    917.8mV
165.2ps   982.7mV    953.4mV    1.024V
215.6ps   1.037V     1.011V     1.082V
279.6ps   1.069V     1.05V      1.117V
530ps     1.101V     1.085V     1.145V
1.262ns   1.104V     1.087V     1.14V
[Falling Waveform]
R_fixture = 50.000
V_fixture = 0.895
V_fixture_min = 0.882
V_fixture_max = 0.901
|  time   V(typ)   V(min)   V(max)
0s        1.104V     1.087V     1.139V
26.1ps    1.1V       1.085V     1.13V
45.1ps    1.087V     1.08V      1.094V
83.7ps    1.012V     1.038V     960.5mV
144.8ps   854.5mV    919.1mV    773.5mV
179.2ps   791.2mV    860.9mV    716.6mV
228.5ps   734.6mV    799.5mV    681.4mV
306.8ps   697.8mV    747.1mV    665.2mV
418.4ps   688.5mV    721.7mV    662.1mV
1.262ns   696mV      720.2mV    665.3mV
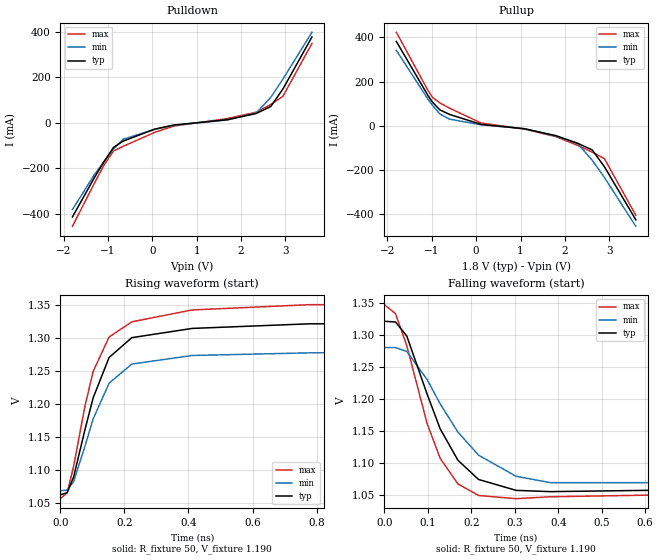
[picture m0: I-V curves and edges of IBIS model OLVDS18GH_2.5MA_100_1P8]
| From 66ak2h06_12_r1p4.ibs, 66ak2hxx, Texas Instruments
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[Model]   OLVDS18GH_2.5MA_100_1P8
Model_type   Output
Polarity   Non-Inverting
Cref =  15.0001pF
Rref =  101.0000M
Vref =  0V
Vmeas =  1.08V
C_comp   1p   1p   1p
[Temperature Range]   25   125   -40
[Voltage Range]   1.8   1.62   1.98
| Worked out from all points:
|   slope of the pulldown table from 0 to 0.27 V, typ, clamps not added: 18.5 ohm
|   slope of the pullup table from 0 to 0.27 V, typ, clamps not added: 28.5 ohm
|   rising waveform, R_fixture 50, V_fixture 1.190: 20-80 % time 96.3ps typ, 98.4ps min, 88.9ps max; typ from 1.06 V to 1.32 V
|   falling waveform, R_fixture 50, V_fixture 1.190: 20-80 % time 89.6ps typ, 126ps min, 74.3ps max; typ from 1.32 V to 1.06 V
[Pulldown]
|   voltage   I(typ)   I(min)   I(max)
-1.8V     -414.2mA   -381.7mA   -455.5mA
-1.309V   -242.8mA   -229.5mA   -267.6mA
-1.091V   -171.7mA   -172.2mA   -186.9mA
-872.7mV  -108mA     -114.6mA   -124mA
-654.5mV  -80.3mA    -72.2mA    -103.3mA
54.55mV   -27.77mA   -28.8mA    -42.11mA
490.9mV   -9.55mA    -10.78mA   -13.85mA
1.691V    13.74mA    12.58mA    18.5mA
2.345V    41.17mA    43.63mA    46.95mA
2.673V    72.04mA    112.4mA    80.87mA
2.945V    148.7mA    192.4mA    116.5mA
3.6V      377.9mA    398.6mA    349.6mA
[Pullup]
|   voltage   I(typ)   I(min)   I(max)
-1.8V     382.3mA    341.9mA    423.6mA
-1.091V   138.4mA    121.6mA    161.2mA
-981.8mV  105.9mA    91.31mA    127.7mA
-818.2mV  71.62mA    52.85mA    103mA
-600mV    51.06mA    29.57mA    79.47mA
109.1mV   5.985mA    4.072mA    12.23mA
1.091V    -14.04mA   -13.34mA   -15.54mA
1.8V      -45.3mA    -47.42mA   -49.81mA
2.291V    -79.96mA   -82.09mA   -89.75mA
2.618V    -110.2mA   -157mA     -120.1mA
2.891V    -186mA     -234.8mA   -149.4mA
3.6V      -427mA     -456.3mA   -406.3mA
[Ramp]
| variable   typ   min   max
dV/dt_f   10.572m/1.321636n   3.588m/0.90402219n   4.968m/0.64676674n
dV/dt_r   5.31m/1.1342577n   3.408m/3.4737588n   4.548m/0.61241385n
R_load = 50
[Rising Waveform]
R_fixture = 50
V_fixture = 1.190
V_fixture_min = 1.1743
V_fixture_max = 1.20176
|   time   V(typ)   V(min)   V(max)
0s        1.063V     1.069V     1.057V
20.8ps    1.066V     1.07V      1.066V
41.2ps    1.09V      1.083V     1.106V
76.8ps    1.162V     1.137V     1.198V
102.3ps   1.21V      1.178V     1.25V
152ps     1.271V     1.232V     1.302V
222.9ps   1.301V     1.261V     1.325V
411.5ps   1.315V     1.274V     1.343V
778.8ps   1.322V     1.278V     1.351V
4.921ns   1.321V     1.28V      1.347V
[Falling Waveform]
R_fixture = 50
V_fixture = 1.190
V_fixture_min = 1.1743
V_fixture_max = 1.20176
|   time   V(typ)   V(min)   V(max)
0s        1.321V     1.28V      1.347V
25.7ps    1.32V      1.28V      1.333V
51.6ps    1.298V     1.274V     1.283V
98.5ps    1.207V     1.23V      1.161V
128.5ps   1.153V     1.192V     1.107V
169.3ps   1.104V     1.148V     1.067V
216.7ps   1.074V     1.112V     1.049V
303.1ps   1.057V     1.079V     1.044V
382.4ps   1.055V     1.069V     1.047V
1.262ns   1.063V     1.069V     1.057V
